VERSION 5.7 ;
  NOWIREEXTENSIONATPIN ON ;
  DIVIDERCHAR "/" ;
  BUSBITCHARS "[]" ;
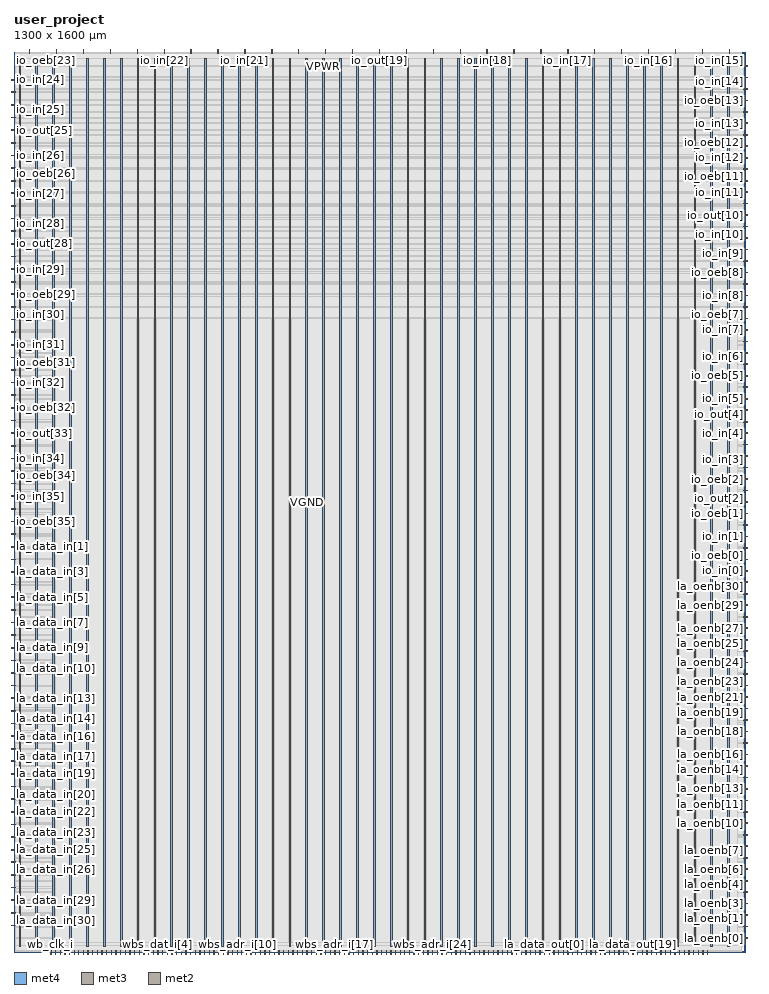
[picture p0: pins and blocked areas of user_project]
MACRO user_project
  CLASS BLOCK ;
  FOREIGN user_project ;
  ORIGIN 0.000 0.000 ;
  SIZE 1300.000 BY 1600.000 ;
  PIN VGND
    DIRECTION INOUT ;
    USE GROUND ;
    PORT
      LAYER met4 ;
        RECT 38.970 10.640 42.070 1588.720 ;
    END
    PORT
      LAYER met4 ;
        RECT 98.970 10.640 102.070 1588.720 ;
    END
    PORT
      LAYER met4 ;
        RECT 158.970 10.640 162.070 1588.720 ;
    END
    PORT
      LAYER met4 ;
        RECT 218.970 10.640 222.070 1588.720 ;
    END
    PORT
      LAYER met4 ;
        RECT 278.970 10.640 282.070 1588.720 ;
    END
    PORT
      LAYER met4 ;
        RECT 338.970 10.640 342.070 1588.720 ;
    END
    PORT
      LAYER met4 ;
        RECT 398.970 10.640 402.070 1588.720 ;
    END
    PORT
      LAYER met4 ;
        RECT 458.970 10.640 462.070 1588.720 ;
    END
    PORT
      LAYER met4 ;
        RECT 518.970 10.640 522.070 1588.720 ;
    END
    PORT
      LAYER met4 ;
        RECT 578.970 10.640 582.070 1588.720 ;
    END
    PORT
      LAYER met4 ;
        RECT 638.970 10.640 642.070 1588.720 ;
    END
    PORT
      LAYER met4 ;
        RECT 698.970 10.640 702.070 1588.720 ;
    END
    PORT
      LAYER met4 ;
        RECT 758.970 10.640 762.070 1588.720 ;
    END
    PORT
      LAYER met4 ;
        RECT 818.970 10.640 822.070 1588.720 ;
    END
    PORT
      LAYER met4 ;
        RECT 878.970 10.640 882.070 1588.720 ;
    END
    PORT
      LAYER met4 ;
        RECT 938.970 10.640 942.070 1588.720 ;
    END
    PORT
      LAYER met4 ;
        RECT 998.970 10.640 1002.070 1588.720 ;
    END
    PORT
      LAYER met4 ;
        RECT 1058.970 10.640 1062.070 1588.720 ;
    END
    PORT
      LAYER met4 ;
        RECT 1118.970 10.640 1122.070 1588.720 ;
    END
    PORT
      LAYER met4 ;
        RECT 1178.970 10.640 1182.070 1588.720 ;
    END
    PORT
      LAYER met4 ;
        RECT 1238.970 10.640 1242.070 1588.720 ;
    END
  END VGND
  PIN VPWR
    DIRECTION INOUT ;
    USE POWER ;
    PORT
      LAYER met4 ;
        RECT 8.970 10.640 12.070 1588.720 ;
    END
    PORT
      LAYER met4 ;
        RECT 68.970 10.640 72.070 1588.720 ;
    END
    PORT
      LAYER met4 ;
        RECT 128.970 10.640 132.070 1588.720 ;
    END
    PORT
      LAYER met4 ;
        RECT 188.970 10.640 192.070 1588.720 ;
    END
    PORT
      LAYER met4 ;
        RECT 248.970 10.640 252.070 1588.720 ;
    END
    PORT
      LAYER met4 ;
        RECT 308.970 10.640 312.070 1588.720 ;
    END
    PORT
      LAYER met4 ;
        RECT 368.970 10.640 372.070 1588.720 ;
    END
    PORT
      LAYER met4 ;
        RECT 428.970 10.640 432.070 1588.720 ;
    END
    PORT
      LAYER met4 ;
        RECT 488.970 10.640 492.070 1588.720 ;
    END
    PORT
      LAYER met4 ;
        RECT 548.970 10.640 552.070 1588.720 ;
    END
    PORT
      LAYER met4 ;
        RECT 608.970 10.640 612.070 1588.720 ;
    END
    PORT
      LAYER met4 ;
        RECT 668.970 10.640 672.070 1588.720 ;
    END
    PORT
      LAYER met4 ;
        RECT 728.970 10.640 732.070 1588.720 ;
    END
    PORT
      LAYER met4 ;
        RECT 788.970 10.640 792.070 1588.720 ;
    END
    PORT
      LAYER met4 ;
        RECT 848.970 10.640 852.070 1588.720 ;
    END
    PORT
      LAYER met4 ;
        RECT 908.970 10.640 912.070 1588.720 ;
    END
    PORT
      LAYER met4 ;
        RECT 968.970 10.640 972.070 1588.720 ;
    END
    PORT
      LAYER met4 ;
        RECT 1028.970 10.640 1032.070 1588.720 ;
    END
    PORT
      LAYER met4 ;
        RECT 1088.970 10.640 1092.070 1588.720 ;
    END
    PORT
      LAYER met4 ;
        RECT 1148.970 10.640 1152.070 1588.720 ;
    END
    PORT
      LAYER met4 ;
        RECT 1208.970 10.640 1212.070 1588.720 ;
    END
    PORT
      LAYER met4 ;
        RECT 1268.970 10.640 1272.070 1588.720 ;
    END
  END VPWR
  PIN io_in[0]
    DIRECTION INPUT ;
    USE SIGNAL ;
    PORT
      LAYER met3 ;
        RECT 1297.600 677.020 1304.800 678.220 ;
    END
  END io_in[0]
  PIN io_in[10]
    DIRECTION INPUT ;
    USE SIGNAL ;
    PORT
      LAYER met3 ;
        RECT 1297.600 1289.020 1304.800 1290.220 ;
    END
  END io_in[10]
  PIN io_in[11]
    DIRECTION INPUT ;
    USE SIGNAL ;
    PORT
      LAYER met3 ;
        RECT 1297.600 1350.220 1304.800 1351.420 ;
    END
  END io_in[11]
  PIN io_in[12]
    DIRECTION INPUT ;
    USE SIGNAL ;
    PORT
      LAYER met3 ;
        RECT 1297.600 1411.420 1304.800 1412.620 ;
    END
  END io_in[12]
  PIN io_in[13]
    DIRECTION INPUT ;
    USE SIGNAL ;
    PORT
      LAYER met3 ;
        RECT 1297.600 1472.620 1304.800 1473.820 ;
    END
  END io_in[13]
  PIN io_in[14]
    DIRECTION INPUT ;
    USE SIGNAL ;
    PORT
      LAYER met3 ;
        RECT 1297.600 1533.820 1304.800 1535.020 ;
    END
  END io_in[14]
  PIN io_in[15]
    DIRECTION INPUT ;
    USE SIGNAL ;
    PORT
      LAYER met2 ;
        RECT 1271.390 1597.600 1271.950 1604.800 ;
    END
  END io_in[15]
  PIN io_in[16]
    DIRECTION INPUT ;
    USE SIGNAL ;
    PORT
      LAYER met2 ;
        RECT 1127.870 1597.600 1128.430 1604.800 ;
    END
  END io_in[16]
  PIN io_in[17]
    DIRECTION INPUT ;
    USE SIGNAL ;
    PORT
      LAYER met2 ;
        RECT 984.350 1597.600 984.910 1604.800 ;
    END
  END io_in[17]
  PIN io_in[18]
    DIRECTION INPUT ;
    USE SIGNAL ;
    PORT
      LAYER met2 ;
        RECT 840.830 1597.600 841.390 1604.800 ;
    END
  END io_in[18]
  PIN io_in[19]
    DIRECTION INPUT ;
    USE SIGNAL ;
    PORT
      LAYER met2 ;
        RECT 697.310 1597.600 697.870 1604.800 ;
    END
  END io_in[19]
  PIN io_in[1]
    DIRECTION INPUT ;
    USE SIGNAL ;
    PORT
      LAYER met3 ;
        RECT 1297.600 738.220 1304.800 739.420 ;
    END
  END io_in[1]
  PIN io_in[20]
    DIRECTION INPUT ;
    USE SIGNAL ;
    PORT
      LAYER met2 ;
        RECT 553.790 1597.600 554.350 1604.800 ;
    END
  END io_in[20]
  PIN io_in[21]
    DIRECTION INPUT ;
    USE SIGNAL ;
    PORT
      LAYER met2 ;
        RECT 410.270 1597.600 410.830 1604.800 ;
    END
  END io_in[21]
  PIN io_in[22]
    DIRECTION INPUT ;
    USE SIGNAL ;
    PORT
      LAYER met2 ;
        RECT 266.750 1597.600 267.310 1604.800 ;
    END
  END io_in[22]
  PIN io_in[23]
    DIRECTION INPUT ;
    USE SIGNAL ;
    PORT
      LAYER met2 ;
        RECT 123.230 1597.600 123.790 1604.800 ;
    END
  END io_in[23]
  PIN io_in[24]
    DIRECTION INPUT ;
    USE SIGNAL ;
    PORT
      LAYER met3 ;
        RECT -4.800 1550.140 2.400 1551.340 ;
    END
  END io_in[24]
  PIN io_in[25]
    DIRECTION INPUT ;
    USE SIGNAL ;
    PORT
      LAYER met3 ;
        RECT -4.800 1482.820 2.400 1484.020 ;
    END
  END io_in[25]
  PIN io_in[26]
    DIRECTION INPUT ;
    USE SIGNAL ;
    PORT
      LAYER met3 ;
        RECT -4.800 1415.500 2.400 1416.700 ;
    END
  END io_in[26]
  PIN io_in[27]
    DIRECTION INPUT ;
    USE SIGNAL ;
    PORT
      LAYER met3 ;
        RECT -4.800 1348.180 2.400 1349.380 ;
    END
  END io_in[27]
  PIN io_in[28]
    DIRECTION INPUT ;
    USE SIGNAL ;
    PORT
      LAYER met3 ;
        RECT -4.800 1280.860 2.400 1282.060 ;
    END
  END io_in[28]
  PIN io_in[29]
    DIRECTION INPUT ;
    USE SIGNAL ;
    PORT
      LAYER met3 ;
        RECT -4.800 1213.540 2.400 1214.740 ;
    END
  END io_in[29]
  PIN io_in[2]
    DIRECTION INPUT ;
    USE SIGNAL ;
    PORT
      LAYER met3 ;
        RECT 1297.600 799.420 1304.800 800.620 ;
    END
  END io_in[2]
  PIN io_in[30]
    DIRECTION INPUT ;
    USE SIGNAL ;
    PORT
      LAYER met3 ;
        RECT -4.800 1146.220 2.400 1147.420 ;
    END
  END io_in[30]
  PIN io_in[31]
    DIRECTION INPUT ;
    USE SIGNAL ;
    PORT
      LAYER met3 ;
        RECT -4.800 1078.900 2.400 1080.100 ;
    END
  END io_in[31]
  PIN io_in[32]
    DIRECTION INPUT ;
    USE SIGNAL ;
    PORT
      LAYER met3 ;
        RECT -4.800 1011.580 2.400 1012.780 ;
    END
  END io_in[32]
  PIN io_in[33]
    DIRECTION INPUT ;
    USE SIGNAL ;
    PORT
      LAYER met3 ;
        RECT -4.800 944.260 2.400 945.460 ;
    END
  END io_in[33]
  PIN io_in[34]
    DIRECTION INPUT ;
    USE SIGNAL ;
    PORT
      LAYER met3 ;
        RECT -4.800 876.940 2.400 878.140 ;
    END
  END io_in[34]
  PIN io_in[35]
    DIRECTION INPUT ;
    USE SIGNAL ;
    PORT
      LAYER met3 ;
        RECT -4.800 809.620 2.400 810.820 ;
    END
  END io_in[35]
  PIN io_in[3]
    DIRECTION INPUT ;
    USE SIGNAL ;
    PORT
      LAYER met3 ;
        RECT 1297.600 860.620 1304.800 861.820 ;
    END
  END io_in[3]
  PIN io_in[4]
    DIRECTION INPUT ;
    USE SIGNAL ;
    PORT
      LAYER met3 ;
        RECT 1297.600 921.820 1304.800 923.020 ;
    END
  END io_in[4]
  PIN io_in[5]
    DIRECTION INPUT ;
    USE SIGNAL ;
    PORT
      LAYER met3 ;
        RECT 1297.600 983.020 1304.800 984.220 ;
    END
  END io_in[5]
  PIN io_in[6]
    DIRECTION INPUT ;
    USE SIGNAL ;
    PORT
      LAYER met3 ;
        RECT 1297.600 1044.220 1304.800 1045.420 ;
    END
  END io_in[6]
  PIN io_in[7]
    DIRECTION INPUT ;
    USE SIGNAL ;
    PORT
      LAYER met3 ;
        RECT 1297.600 1105.420 1304.800 1106.620 ;
    END
  END io_in[7]
  PIN io_in[8]
    DIRECTION INPUT ;
    USE SIGNAL ;
    PORT
      LAYER met3 ;
        RECT 1297.600 1166.620 1304.800 1167.820 ;
    END
  END io_in[8]
  PIN io_in[9]
    DIRECTION INPUT ;
    USE SIGNAL ;
    PORT
      LAYER met3 ;
        RECT 1297.600 1227.820 1304.800 1229.020 ;
    END
  END io_in[9]
  PIN io_oeb[0]
    DIRECTION OUTPUT ;
    USE SIGNAL ;
    ANTENNADIFFAREA 2.673000 ;
    PORT
      LAYER met3 ;
        RECT 1297.600 717.820 1304.800 719.020 ;
    END
  END io_oeb[0]
  PIN io_oeb[10]
    DIRECTION OUTPUT ;
    USE SIGNAL ;
    ANTENNADIFFAREA 2.673000 ;
    PORT
      LAYER met3 ;
        RECT 1297.600 1329.820 1304.800 1331.020 ;
    END
  END io_oeb[10]
  PIN io_oeb[11]
    DIRECTION OUTPUT ;
    USE SIGNAL ;
    ANTENNADIFFAREA 2.673000 ;
    PORT
      LAYER met3 ;
        RECT 1297.600 1391.020 1304.800 1392.220 ;
    END
  END io_oeb[11]
  PIN io_oeb[12]
    DIRECTION OUTPUT ;
    USE SIGNAL ;
    ANTENNADIFFAREA 2.673000 ;
    PORT
      LAYER met3 ;
        RECT 1297.600 1452.220 1304.800 1453.420 ;
    END
  END io_oeb[12]
  PIN io_oeb[13]
    DIRECTION OUTPUT ;
    USE SIGNAL ;
    ANTENNADIFFAREA 2.673000 ;
    PORT
      LAYER met3 ;
        RECT 1297.600 1513.420 1304.800 1514.620 ;
    END
  END io_oeb[13]
  PIN io_oeb[14]
    DIRECTION OUTPUT ;
    USE SIGNAL ;
    ANTENNADIFFAREA 2.673000 ;
    PORT
      LAYER met3 ;
        RECT 1297.600 1574.620 1304.800 1575.820 ;
    END
  END io_oeb[14]
  PIN io_oeb[15]
    DIRECTION OUTPUT ;
    USE SIGNAL ;
    ANTENNADIFFAREA 2.673000 ;
    PORT
      LAYER met2 ;
        RECT 1175.710 1597.600 1176.270 1604.800 ;
    END
  END io_oeb[15]
  PIN io_oeb[16]
    DIRECTION OUTPUT ;
    USE SIGNAL ;
    ANTENNADIFFAREA 2.673000 ;
    PORT
      LAYER met2 ;
        RECT 1032.190 1597.600 1032.750 1604.800 ;
    END
  END io_oeb[16]
  PIN io_oeb[17]
    DIRECTION OUTPUT ;
    USE SIGNAL ;
    ANTENNADIFFAREA 2.673000 ;
    PORT
      LAYER met2 ;
        RECT 888.670 1597.600 889.230 1604.800 ;
    END
  END io_oeb[17]
  PIN io_oeb[18]
    DIRECTION OUTPUT ;
    USE SIGNAL ;
    ANTENNADIFFAREA 2.673000 ;
    PORT
      LAYER met2 ;
        RECT 745.150 1597.600 745.710 1604.800 ;
    END
  END io_oeb[18]
  PIN io_oeb[19]
    DIRECTION OUTPUT ;
    USE SIGNAL ;
    ANTENNADIFFAREA 2.673000 ;
    PORT
      LAYER met2 ;
        RECT 601.630 1597.600 602.190 1604.800 ;
    END
  END io_oeb[19]
  PIN io_oeb[1]
    DIRECTION OUTPUT ;
    USE SIGNAL ;
    ANTENNADIFFAREA 2.673000 ;
    PORT
      LAYER met3 ;
        RECT 1297.600 779.020 1304.800 780.220 ;
    END
  END io_oeb[1]
  PIN io_oeb[20]
    DIRECTION OUTPUT ;
    USE SIGNAL ;
    ANTENNADIFFAREA 2.673000 ;
    PORT
      LAYER met2 ;
        RECT 458.110 1597.600 458.670 1604.800 ;
    END
  END io_oeb[20]
  PIN io_oeb[21]
    DIRECTION OUTPUT ;
    USE SIGNAL ;
    ANTENNADIFFAREA 2.673000 ;
    PORT
      LAYER met2 ;
        RECT 314.590 1597.600 315.150 1604.800 ;
    END
  END io_oeb[21]
  PIN io_oeb[22]
    DIRECTION OUTPUT ;
    USE SIGNAL ;
    ANTENNADIFFAREA 2.673000 ;
    PORT
      LAYER met2 ;
        RECT 171.070 1597.600 171.630 1604.800 ;
    END
  END io_oeb[22]
  PIN io_oeb[23]
    DIRECTION OUTPUT ;
    USE SIGNAL ;
    ANTENNADIFFAREA 2.673000 ;
    PORT
      LAYER met2 ;
        RECT 27.550 1597.600 28.110 1604.800 ;
    END
  END io_oeb[23]
  PIN io_oeb[24]
    DIRECTION OUTPUT ;
    USE SIGNAL ;
    ANTENNADIFFAREA 2.673000 ;
    PORT
      LAYER met3 ;
        RECT -4.800 1505.260 2.400 1506.460 ;
    END
  END io_oeb[24]
  PIN io_oeb[25]
    DIRECTION OUTPUT ;
    USE SIGNAL ;
    ANTENNADIFFAREA 2.673000 ;
    PORT
      LAYER met3 ;
        RECT -4.800 1437.940 2.400 1439.140 ;
    END
  END io_oeb[25]
  PIN io_oeb[26]
    DIRECTION OUTPUT ;
    USE SIGNAL ;
    ANTENNADIFFAREA 2.673000 ;
    PORT
      LAYER met3 ;
        RECT -4.800 1370.620 2.400 1371.820 ;
    END
  END io_oeb[26]
  PIN io_oeb[27]
    DIRECTION OUTPUT ;
    USE SIGNAL ;
    ANTENNADIFFAREA 2.673000 ;
    PORT
      LAYER met3 ;
        RECT -4.800 1303.300 2.400 1304.500 ;
    END
  END io_oeb[27]
  PIN io_oeb[28]
    DIRECTION OUTPUT ;
    USE SIGNAL ;
    ANTENNADIFFAREA 2.673000 ;
    PORT
      LAYER met3 ;
        RECT -4.800 1235.980 2.400 1237.180 ;
    END
  END io_oeb[28]
  PIN io_oeb[29]
    DIRECTION OUTPUT ;
    USE SIGNAL ;
    ANTENNADIFFAREA 2.673000 ;
    PORT
      LAYER met3 ;
        RECT -4.800 1168.660 2.400 1169.860 ;
    END
  END io_oeb[29]
  PIN io_oeb[2]
    DIRECTION OUTPUT ;
    USE SIGNAL ;
    ANTENNADIFFAREA 2.673000 ;
    PORT
      LAYER met3 ;
        RECT 1297.600 840.220 1304.800 841.420 ;
    END
  END io_oeb[2]
  PIN io_oeb[30]
    DIRECTION OUTPUT ;
    USE SIGNAL ;
    PORT
      LAYER met3 ;
        RECT -4.800 1101.340 2.400 1102.540 ;
    END
  END io_oeb[30]
  PIN io_oeb[31]
    DIRECTION OUTPUT ;
    USE SIGNAL ;
    PORT
      LAYER met3 ;
        RECT -4.800 1034.020 2.400 1035.220 ;
    END
  END io_oeb[31]
  PIN io_oeb[32]
    DIRECTION OUTPUT ;
    USE SIGNAL ;
    PORT
      LAYER met3 ;
        RECT -4.800 966.700 2.400 967.900 ;
    END
  END io_oeb[32]
  PIN io_oeb[33]
    DIRECTION OUTPUT ;
    USE SIGNAL ;
    PORT
      LAYER met3 ;
        RECT -4.800 899.380 2.400 900.580 ;
    END
  END io_oeb[33]
  PIN io_oeb[34]
    DIRECTION OUTPUT ;
    USE SIGNAL ;
    PORT
      LAYER met3 ;
        RECT -4.800 832.060 2.400 833.260 ;
    END
  END io_oeb[34]
  PIN io_oeb[35]
    DIRECTION OUTPUT ;
    USE SIGNAL ;
    PORT
      LAYER met3 ;
        RECT -4.800 764.740 2.400 765.940 ;
    END
  END io_oeb[35]
  PIN io_oeb[3]
    DIRECTION OUTPUT ;
    USE SIGNAL ;
    ANTENNADIFFAREA 2.673000 ;
    PORT
      LAYER met3 ;
        RECT 1297.600 901.420 1304.800 902.620 ;
    END
  END io_oeb[3]
  PIN io_oeb[4]
    DIRECTION OUTPUT ;
    USE SIGNAL ;
    ANTENNADIFFAREA 2.673000 ;
    PORT
      LAYER met3 ;
        RECT 1297.600 962.620 1304.800 963.820 ;
    END
  END io_oeb[4]
  PIN io_oeb[5]
    DIRECTION OUTPUT ;
    USE SIGNAL ;
    ANTENNADIFFAREA 2.673000 ;
    PORT
      LAYER met3 ;
        RECT 1297.600 1023.820 1304.800 1025.020 ;
    END
  END io_oeb[5]
  PIN io_oeb[6]
    DIRECTION OUTPUT ;
    USE SIGNAL ;
    ANTENNADIFFAREA 2.673000 ;
    PORT
      LAYER met3 ;
        RECT 1297.600 1085.020 1304.800 1086.220 ;
    END
  END io_oeb[6]
  PIN io_oeb[7]
    DIRECTION OUTPUT ;
    USE SIGNAL ;
    ANTENNADIFFAREA 2.673000 ;
    PORT
      LAYER met3 ;
        RECT 1297.600 1146.220 1304.800 1147.420 ;
    END
  END io_oeb[7]
  PIN io_oeb[8]
    DIRECTION OUTPUT ;
    USE SIGNAL ;
    ANTENNADIFFAREA 2.673000 ;
    PORT
      LAYER met3 ;
        RECT 1297.600 1207.420 1304.800 1208.620 ;
    END
  END io_oeb[8]
  PIN io_oeb[9]
    DIRECTION OUTPUT ;
    USE SIGNAL ;
    ANTENNADIFFAREA 2.673000 ;
    PORT
      LAYER met3 ;
        RECT 1297.600 1268.620 1304.800 1269.820 ;
    END
  END io_oeb[9]
  PIN io_out[0]
    DIRECTION OUTPUT ;
    USE SIGNAL ;
    ANTENNADIFFAREA 2.673000 ;
    PORT
      LAYER met3 ;
        RECT 1297.600 697.420 1304.800 698.620 ;
    END
  END io_out[0]
  PIN io_out[10]
    DIRECTION OUTPUT ;
    USE SIGNAL ;
    ANTENNADIFFAREA 2.673000 ;
    PORT
      LAYER met3 ;
        RECT 1297.600 1309.420 1304.800 1310.620 ;
    END
  END io_out[10]
  PIN io_out[11]
    DIRECTION OUTPUT ;
    USE SIGNAL ;
    ANTENNADIFFAREA 2.673000 ;
    PORT
      LAYER met3 ;
        RECT 1297.600 1370.620 1304.800 1371.820 ;
    END
  END io_out[11]
  PIN io_out[12]
    DIRECTION OUTPUT ;
    USE SIGNAL ;
    ANTENNADIFFAREA 2.673000 ;
    PORT
      LAYER met3 ;
        RECT 1297.600 1431.820 1304.800 1433.020 ;
    END
  END io_out[12]
  PIN io_out[13]
    DIRECTION OUTPUT ;
    USE SIGNAL ;
    ANTENNADIFFAREA 2.673000 ;
    PORT
      LAYER met3 ;
        RECT 1297.600 1493.020 1304.800 1494.220 ;
    END
  END io_out[13]
  PIN io_out[14]
    DIRECTION OUTPUT ;
    USE SIGNAL ;
    ANTENNADIFFAREA 2.673000 ;
    PORT
      LAYER met3 ;
        RECT 1297.600 1554.220 1304.800 1555.420 ;
    END
  END io_out[14]
  PIN io_out[15]
    DIRECTION OUTPUT ;
    USE SIGNAL ;
    ANTENNADIFFAREA 2.673000 ;
    PORT
      LAYER met2 ;
        RECT 1223.550 1597.600 1224.110 1604.800 ;
    END
  END io_out[15]
  PIN io_out[16]
    DIRECTION OUTPUT ;
    USE SIGNAL ;
    ANTENNADIFFAREA 2.673000 ;
    PORT
      LAYER met2 ;
        RECT 1080.030 1597.600 1080.590 1604.800 ;
    END
  END io_out[16]
  PIN io_out[17]
    DIRECTION OUTPUT ;
    USE SIGNAL ;
    ANTENNADIFFAREA 2.673000 ;
    PORT
      LAYER met2 ;
        RECT 936.510 1597.600 937.070 1604.800 ;
    END
  END io_out[17]
  PIN io_out[18]
    DIRECTION OUTPUT ;
    USE SIGNAL ;
    ANTENNADIFFAREA 2.673000 ;
    PORT
      LAYER met2 ;
        RECT 792.990 1597.600 793.550 1604.800 ;
    END
  END io_out[18]
  PIN io_out[19]
    DIRECTION OUTPUT ;
    USE SIGNAL ;
    ANTENNADIFFAREA 2.673000 ;
    PORT
      LAYER met2 ;
        RECT 649.470 1597.600 650.030 1604.800 ;
    END
  END io_out[19]
  PIN io_out[1]
    DIRECTION OUTPUT ;
    USE SIGNAL ;
    ANTENNADIFFAREA 2.673000 ;
    PORT
      LAYER met3 ;
        RECT 1297.600 758.620 1304.800 759.820 ;
    END
  END io_out[1]
  PIN io_out[20]
    DIRECTION OUTPUT ;
    USE SIGNAL ;
    ANTENNADIFFAREA 2.673000 ;
    PORT
      LAYER met2 ;
        RECT 505.950 1597.600 506.510 1604.800 ;
    END
  END io_out[20]
  PIN io_out[21]
    DIRECTION OUTPUT ;
    USE SIGNAL ;
    ANTENNADIFFAREA 2.673000 ;
    PORT
      LAYER met2 ;
        RECT 362.430 1597.600 362.990 1604.800 ;
    END
  END io_out[21]
  PIN io_out[22]
    DIRECTION OUTPUT ;
    USE SIGNAL ;
    ANTENNADIFFAREA 2.673000 ;
    PORT
      LAYER met2 ;
        RECT 218.910 1597.600 219.470 1604.800 ;
    END
  END io_out[22]
  PIN io_out[23]
    DIRECTION OUTPUT ;
    USE SIGNAL ;
    ANTENNADIFFAREA 2.673000 ;
    PORT
      LAYER met2 ;
        RECT 75.390 1597.600 75.950 1604.800 ;
    END
  END io_out[23]
  PIN io_out[24]
    DIRECTION OUTPUT ;
    USE SIGNAL ;
    ANTENNADIFFAREA 2.673000 ;
    PORT
      LAYER met3 ;
        RECT -4.800 1527.700 2.400 1528.900 ;
    END
  END io_out[24]
  PIN io_out[25]
    DIRECTION OUTPUT ;
    USE SIGNAL ;
    ANTENNADIFFAREA 2.673000 ;
    PORT
      LAYER met3 ;
        RECT -4.800 1460.380 2.400 1461.580 ;
    END
  END io_out[25]
  PIN io_out[26]
    DIRECTION OUTPUT ;
    USE SIGNAL ;
    ANTENNADIFFAREA 2.673000 ;
    PORT
      LAYER met3 ;
        RECT -4.800 1393.060 2.400 1394.260 ;
    END
  END io_out[26]
  PIN io_out[27]
    DIRECTION OUTPUT ;
    USE SIGNAL ;
    ANTENNADIFFAREA 2.673000 ;
    PORT
      LAYER met3 ;
        RECT -4.800 1325.740 2.400 1326.940 ;
    END
  END io_out[27]
  PIN io_out[28]
    DIRECTION OUTPUT ;
    USE SIGNAL ;
    ANTENNADIFFAREA 2.673000 ;
    PORT
      LAYER met3 ;
        RECT -4.800 1258.420 2.400 1259.620 ;
    END
  END io_out[28]
  PIN io_out[29]
    DIRECTION OUTPUT ;
    USE SIGNAL ;
    ANTENNADIFFAREA 2.673000 ;
    PORT
      LAYER met3 ;
        RECT -4.800 1191.100 2.400 1192.300 ;
    END
  END io_out[29]
  PIN io_out[2]
    DIRECTION OUTPUT ;
    USE SIGNAL ;
    ANTENNADIFFAREA 2.673000 ;
    PORT
      LAYER met3 ;
        RECT 1297.600 819.820 1304.800 821.020 ;
    END
  END io_out[2]
  PIN io_out[30]
    DIRECTION OUTPUT ;
    USE SIGNAL ;
    PORT
      LAYER met3 ;
        RECT -4.800 1123.780 2.400 1124.980 ;
    END
  END io_out[30]
  PIN io_out[31]
    DIRECTION OUTPUT ;
    USE SIGNAL ;
    PORT
      LAYER met3 ;
        RECT -4.800 1056.460 2.400 1057.660 ;
    END
  END io_out[31]
  PIN io_out[32]
    DIRECTION OUTPUT ;
    USE SIGNAL ;
    PORT
      LAYER met3 ;
        RECT -4.800 989.140 2.400 990.340 ;
    END
  END io_out[32]
  PIN io_out[33]
    DIRECTION OUTPUT ;
    USE SIGNAL ;
    PORT
      LAYER met3 ;
        RECT -4.800 921.820 2.400 923.020 ;
    END
  END io_out[33]
  PIN io_out[34]
    DIRECTION OUTPUT ;
    USE SIGNAL ;
    PORT
      LAYER met3 ;
        RECT -4.800 854.500 2.400 855.700 ;
    END
  END io_out[34]
  PIN io_out[35]
    DIRECTION OUTPUT ;
    USE SIGNAL ;
    PORT
      LAYER met3 ;
        RECT -4.800 787.180 2.400 788.380 ;
    END
  END io_out[35]
  PIN io_out[3]
    DIRECTION OUTPUT ;
    USE SIGNAL ;
    ANTENNADIFFAREA 2.673000 ;
    PORT
      LAYER met3 ;
        RECT 1297.600 881.020 1304.800 882.220 ;
    END
  END io_out[3]
  PIN io_out[4]
    DIRECTION OUTPUT ;
    USE SIGNAL ;
    ANTENNADIFFAREA 2.673000 ;
    PORT
      LAYER met3 ;
        RECT 1297.600 942.220 1304.800 943.420 ;
    END
  END io_out[4]
  PIN io_out[5]
    DIRECTION OUTPUT ;
    USE SIGNAL ;
    ANTENNADIFFAREA 2.673000 ;
    PORT
      LAYER met3 ;
        RECT 1297.600 1003.420 1304.800 1004.620 ;
    END
  END io_out[5]
  PIN io_out[6]
    DIRECTION OUTPUT ;
    USE SIGNAL ;
    ANTENNADIFFAREA 2.673000 ;
    PORT
      LAYER met3 ;
        RECT 1297.600 1064.620 1304.800 1065.820 ;
    END
  END io_out[6]
  PIN io_out[7]
    DIRECTION OUTPUT ;
    USE SIGNAL ;
    ANTENNADIFFAREA 2.673000 ;
    PORT
      LAYER met3 ;
        RECT 1297.600 1125.820 1304.800 1127.020 ;
    END
  END io_out[7]
  PIN io_out[8]
    DIRECTION OUTPUT ;
    USE SIGNAL ;
    ANTENNADIFFAREA 2.673000 ;
    PORT
      LAYER met3 ;
        RECT 1297.600 1187.020 1304.800 1188.220 ;
    END
  END io_out[8]
  PIN io_out[9]
    DIRECTION OUTPUT ;
    USE SIGNAL ;
    ANTENNADIFFAREA 2.673000 ;
    PORT
      LAYER met3 ;
        RECT 1297.600 1248.220 1304.800 1249.420 ;
    END
  END io_out[9]
  PIN la_data_in[0]
    DIRECTION INPUT ;
    USE SIGNAL ;
    ANTENNAGATEAREA 0.126000 ;
    PORT
      LAYER met3 ;
        RECT -4.800 742.300 2.400 743.500 ;
    END
  END la_data_in[0]
  PIN la_data_in[10]
    DIRECTION INPUT ;
    USE SIGNAL ;
    ANTENNAGATEAREA 0.126000 ;
    PORT
      LAYER met3 ;
        RECT -4.800 517.900 2.400 519.100 ;
    END
  END la_data_in[10]
  PIN la_data_in[11]
    DIRECTION INPUT ;
    USE SIGNAL ;
    ANTENNAGATEAREA 0.126000 ;
    PORT
      LAYER met3 ;
        RECT -4.800 495.460 2.400 496.660 ;
    END
  END la_data_in[11]
  PIN la_data_in[12]
    DIRECTION INPUT ;
    USE SIGNAL ;
    ANTENNAGATEAREA 0.126000 ;
    PORT
      LAYER met3 ;
        RECT -4.800 473.020 2.400 474.220 ;
    END
  END la_data_in[12]
  PIN la_data_in[13]
    DIRECTION INPUT ;
    USE SIGNAL ;
    ANTENNAGATEAREA 0.126000 ;
    PORT
      LAYER met3 ;
        RECT -4.800 450.580 2.400 451.780 ;
    END
  END la_data_in[13]
  PIN la_data_in[14]
    DIRECTION INPUT ;
    USE SIGNAL ;
    ANTENNAGATEAREA 0.126000 ;
    PORT
      LAYER met3 ;
        RECT -4.800 428.140 2.400 429.340 ;
    END
  END la_data_in[14]
  PIN la_data_in[15]
    DIRECTION INPUT ;
    USE SIGNAL ;
    ANTENNAGATEAREA 0.126000 ;
    PORT
      LAYER met3 ;
        RECT -4.800 405.700 2.400 406.900 ;
    END
  END la_data_in[15]
  PIN la_data_in[16]
    DIRECTION INPUT ;
    USE SIGNAL ;
    ANTENNAGATEAREA 0.126000 ;
    PORT
      LAYER met3 ;
        RECT -4.800 383.260 2.400 384.460 ;
    END
  END la_data_in[16]
  PIN la_data_in[17]
    DIRECTION INPUT ;
    USE SIGNAL ;
    ANTENNAGATEAREA 0.126000 ;
    PORT
      LAYER met3 ;
        RECT -4.800 360.820 2.400 362.020 ;
    END
  END la_data_in[17]
  PIN la_data_in[18]
    DIRECTION INPUT ;
    USE SIGNAL ;
    ANTENNAGATEAREA 0.126000 ;
    PORT
      LAYER met3 ;
        RECT -4.800 338.380 2.400 339.580 ;
    END
  END la_data_in[18]
  PIN la_data_in[19]
    DIRECTION INPUT ;
    USE SIGNAL ;
    ANTENNAGATEAREA 0.126000 ;
    PORT
      LAYER met3 ;
        RECT -4.800 315.940 2.400 317.140 ;
    END
  END la_data_in[19]
  PIN la_data_in[1]
    DIRECTION INPUT ;
    USE SIGNAL ;
    ANTENNAGATEAREA 0.126000 ;
    PORT
      LAYER met3 ;
        RECT -4.800 719.860 2.400 721.060 ;
    END
  END la_data_in[1]
  PIN la_data_in[20]
    DIRECTION INPUT ;
    USE SIGNAL ;
    ANTENNAGATEAREA 0.126000 ;
    PORT
      LAYER met3 ;
        RECT -4.800 293.500 2.400 294.700 ;
    END
  END la_data_in[20]
  PIN la_data_in[21]
    DIRECTION INPUT ;
    USE SIGNAL ;
    ANTENNAGATEAREA 0.126000 ;
    PORT
      LAYER met3 ;
        RECT -4.800 271.060 2.400 272.260 ;
    END
  END la_data_in[21]
  PIN la_data_in[22]
    DIRECTION INPUT ;
    USE SIGNAL ;
    ANTENNAGATEAREA 0.126000 ;
    PORT
      LAYER met3 ;
        RECT -4.800 248.620 2.400 249.820 ;
    END
  END la_data_in[22]
  PIN la_data_in[23]
    DIRECTION INPUT ;
    USE SIGNAL ;
    ANTENNAGATEAREA 0.126000 ;
    PORT
      LAYER met3 ;
        RECT -4.800 226.180 2.400 227.380 ;
    END
  END la_data_in[23]
  PIN la_data_in[24]
    DIRECTION INPUT ;
    USE SIGNAL ;
    ANTENNAGATEAREA 0.126000 ;
    PORT
      LAYER met3 ;
        RECT -4.800 203.740 2.400 204.940 ;
    END
  END la_data_in[24]
  PIN la_data_in[25]
    DIRECTION INPUT ;
    USE SIGNAL ;
    ANTENNAGATEAREA 0.126000 ;
    PORT
      LAYER met3 ;
        RECT -4.800 181.300 2.400 182.500 ;
    END
  END la_data_in[25]
  PIN la_data_in[26]
    DIRECTION INPUT ;
    USE SIGNAL ;
    ANTENNAGATEAREA 0.126000 ;
    PORT
      LAYER met3 ;
        RECT -4.800 158.860 2.400 160.060 ;
    END
  END la_data_in[26]
  PIN la_data_in[27]
    DIRECTION INPUT ;
    USE SIGNAL ;
    ANTENNAGATEAREA 0.126000 ;
    PORT
      LAYER met3 ;
        RECT -4.800 136.420 2.400 137.620 ;
    END
  END la_data_in[27]
  PIN la_data_in[28]
    DIRECTION INPUT ;
    USE SIGNAL ;
    ANTENNAGATEAREA 0.126000 ;
    PORT
      LAYER met3 ;
        RECT -4.800 113.980 2.400 115.180 ;
    END
  END la_data_in[28]
  PIN la_data_in[29]
    DIRECTION INPUT ;
    USE SIGNAL ;
    ANTENNAGATEAREA 0.126000 ;
    PORT
      LAYER met3 ;
        RECT -4.800 91.540 2.400 92.740 ;
    END
  END la_data_in[29]
  PIN la_data_in[2]
    DIRECTION INPUT ;
    USE SIGNAL ;
    ANTENNAGATEAREA 0.126000 ;
    PORT
      LAYER met3 ;
        RECT -4.800 697.420 2.400 698.620 ;
    END
  END la_data_in[2]
  PIN la_data_in[30]
    DIRECTION INPUT ;
    USE SIGNAL ;
    ANTENNAGATEAREA 0.196500 ;
    PORT
      LAYER met3 ;
        RECT -4.800 69.100 2.400 70.300 ;
    END
  END la_data_in[30]
  PIN la_data_in[31]
    DIRECTION INPUT ;
    USE SIGNAL ;
    ANTENNAGATEAREA 0.126000 ;
    PORT
      LAYER met3 ;
        RECT -4.800 46.660 2.400 47.860 ;
    END
  END la_data_in[31]
  PIN la_data_in[3]
    DIRECTION INPUT ;
    USE SIGNAL ;
    ANTENNAGATEAREA 0.126000 ;
    PORT
      LAYER met3 ;
        RECT -4.800 674.980 2.400 676.180 ;
    END
  END la_data_in[3]
  PIN la_data_in[4]
    DIRECTION INPUT ;
    USE SIGNAL ;
    ANTENNAGATEAREA 0.126000 ;
    PORT
      LAYER met3 ;
        RECT -4.800 652.540 2.400 653.740 ;
    END
  END la_data_in[4]
  PIN la_data_in[5]
    DIRECTION INPUT ;
    USE SIGNAL ;
    ANTENNAGATEAREA 0.126000 ;
    PORT
      LAYER met3 ;
        RECT -4.800 630.100 2.400 631.300 ;
    END
  END la_data_in[5]
  PIN la_data_in[6]
    DIRECTION INPUT ;
    USE SIGNAL ;
    ANTENNAGATEAREA 0.126000 ;
    PORT
      LAYER met3 ;
        RECT -4.800 607.660 2.400 608.860 ;
    END
  END la_data_in[6]
  PIN la_data_in[7]
    DIRECTION INPUT ;
    USE SIGNAL ;
    ANTENNAGATEAREA 0.126000 ;
    PORT
      LAYER met3 ;
        RECT -4.800 585.220 2.400 586.420 ;
    END
  END la_data_in[7]
  PIN la_data_in[8]
    DIRECTION INPUT ;
    USE SIGNAL ;
    ANTENNAGATEAREA 0.126000 ;
    PORT
      LAYER met3 ;
        RECT -4.800 562.780 2.400 563.980 ;
    END
  END la_data_in[8]
  PIN la_data_in[9]
    DIRECTION INPUT ;
    USE SIGNAL ;
    ANTENNAGATEAREA 0.126000 ;
    PORT
      LAYER met3 ;
        RECT -4.800 540.340 2.400 541.540 ;
    END
  END la_data_in[9]
  PIN la_data_out[0]
    DIRECTION OUTPUT ;
    USE SIGNAL ;
    PORT
      LAYER met2 ;
        RECT 942.950 -4.800 943.510 2.400 ;
    END
  END la_data_out[0]
  PIN la_data_out[10]
    DIRECTION OUTPUT ;
    USE SIGNAL ;
    PORT
      LAYER met2 ;
        RECT 1025.750 -4.800 1026.310 2.400 ;
    END
  END la_data_out[10]
  PIN la_data_out[11]
    DIRECTION OUTPUT ;
    USE SIGNAL ;
    PORT
      LAYER met2 ;
        RECT 1034.030 -4.800 1034.590 2.400 ;
    END
  END la_data_out[11]
  PIN la_data_out[12]
    DIRECTION OUTPUT ;
    USE SIGNAL ;
    PORT
      LAYER met2 ;
        RECT 1042.310 -4.800 1042.870 2.400 ;
    END
  END la_data_out[12]
  PIN la_data_out[13]
    DIRECTION OUTPUT ;
    USE SIGNAL ;
    PORT
      LAYER met2 ;
        RECT 1050.590 -4.800 1051.150 2.400 ;
    END
  END la_data_out[13]
  PIN la_data_out[14]
    DIRECTION OUTPUT ;
    USE SIGNAL ;
    PORT
      LAYER met2 ;
        RECT 1058.870 -4.800 1059.430 2.400 ;
    END
  END la_data_out[14]
  PIN la_data_out[15]
    DIRECTION OUTPUT ;
    USE SIGNAL ;
    PORT
      LAYER met2 ;
        RECT 1067.150 -4.800 1067.710 2.400 ;
    END
  END la_data_out[15]
  PIN la_data_out[16]
    DIRECTION OUTPUT ;
    USE SIGNAL ;
    PORT
      LAYER met2 ;
        RECT 1075.430 -4.800 1075.990 2.400 ;
    END
  END la_data_out[16]
  PIN la_data_out[17]
    DIRECTION OUTPUT ;
    USE SIGNAL ;
    PORT
      LAYER met2 ;
        RECT 1083.710 -4.800 1084.270 2.400 ;
    END
  END la_data_out[17]
  PIN la_data_out[18]
    DIRECTION OUTPUT ;
    USE SIGNAL ;
    PORT
      LAYER met2 ;
        RECT 1091.990 -4.800 1092.550 2.400 ;
    END
  END la_data_out[18]
  PIN la_data_out[19]
    DIRECTION OUTPUT ;
    USE SIGNAL ;
    PORT
      LAYER met2 ;
        RECT 1100.270 -4.800 1100.830 2.400 ;
    END
  END la_data_out[19]
  PIN la_data_out[1]
    DIRECTION OUTPUT ;
    USE SIGNAL ;
    PORT
      LAYER met2 ;
        RECT 951.230 -4.800 951.790 2.400 ;
    END
  END la_data_out[1]
  PIN la_data_out[20]
    DIRECTION OUTPUT ;
    USE SIGNAL ;
    PORT
      LAYER met2 ;
        RECT 1108.550 -4.800 1109.110 2.400 ;
    END
  END la_data_out[20]
  PIN la_data_out[21]
    DIRECTION OUTPUT ;
    USE SIGNAL ;
    PORT
      LAYER met2 ;
        RECT 1116.830 -4.800 1117.390 2.400 ;
    END
  END la_data_out[21]
  PIN la_data_out[22]
    DIRECTION OUTPUT ;
    USE SIGNAL ;
    PORT
      LAYER met2 ;
        RECT 1125.110 -4.800 1125.670 2.400 ;
    END
  END la_data_out[22]
  PIN la_data_out[23]
    DIRECTION OUTPUT ;
    USE SIGNAL ;
    PORT
      LAYER met2 ;
        RECT 1133.390 -4.800 1133.950 2.400 ;
    END
  END la_data_out[23]
  PIN la_data_out[24]
    DIRECTION OUTPUT ;
    USE SIGNAL ;
    PORT
      LAYER met2 ;
        RECT 1141.670 -4.800 1142.230 2.400 ;
    END
  END la_data_out[24]
  PIN la_data_out[25]
    DIRECTION OUTPUT ;
    USE SIGNAL ;
    PORT
      LAYER met2 ;
        RECT 1149.950 -4.800 1150.510 2.400 ;
    END
  END la_data_out[25]
  PIN la_data_out[26]
    DIRECTION OUTPUT ;
    USE SIGNAL ;
    PORT
      LAYER met2 ;
        RECT 1158.230 -4.800 1158.790 2.400 ;
    END
  END la_data_out[26]
  PIN la_data_out[27]
    DIRECTION OUTPUT ;
    USE SIGNAL ;
    PORT
      LAYER met2 ;
        RECT 1166.510 -4.800 1167.070 2.400 ;
    END
  END la_data_out[27]
  PIN la_data_out[28]
    DIRECTION OUTPUT ;
    USE SIGNAL ;
    PORT
      LAYER met2 ;
        RECT 1174.790 -4.800 1175.350 2.400 ;
    END
  END la_data_out[28]
  PIN la_data_out[29]
    DIRECTION OUTPUT ;
    USE SIGNAL ;
    PORT
      LAYER met2 ;
        RECT 1183.070 -4.800 1183.630 2.400 ;
    END
  END la_data_out[29]
  PIN la_data_out[2]
    DIRECTION OUTPUT ;
    USE SIGNAL ;
    PORT
      LAYER met2 ;
        RECT 959.510 -4.800 960.070 2.400 ;
    END
  END la_data_out[2]
  PIN la_data_out[30]
    DIRECTION OUTPUT ;
    USE SIGNAL ;
    PORT
      LAYER met2 ;
        RECT 1191.350 -4.800 1191.910 2.400 ;
    END
  END la_data_out[30]
  PIN la_data_out[31]
    DIRECTION OUTPUT ;
    USE SIGNAL ;
    PORT
      LAYER met2 ;
        RECT 1199.630 -4.800 1200.190 2.400 ;
    END
  END la_data_out[31]
  PIN la_data_out[3]
    DIRECTION OUTPUT ;
    USE SIGNAL ;
    PORT
      LAYER met2 ;
        RECT 967.790 -4.800 968.350 2.400 ;
    END
  END la_data_out[3]
  PIN la_data_out[4]
    DIRECTION OUTPUT ;
    USE SIGNAL ;
    PORT
      LAYER met2 ;
        RECT 976.070 -4.800 976.630 2.400 ;
    END
  END la_data_out[4]
  PIN la_data_out[5]
    DIRECTION OUTPUT ;
    USE SIGNAL ;
    PORT
      LAYER met2 ;
        RECT 984.350 -4.800 984.910 2.400 ;
    END
  END la_data_out[5]
  PIN la_data_out[6]
    DIRECTION OUTPUT ;
    USE SIGNAL ;
    PORT
      LAYER met2 ;
        RECT 992.630 -4.800 993.190 2.400 ;
    END
  END la_data_out[6]
  PIN la_data_out[7]
    DIRECTION OUTPUT ;
    USE SIGNAL ;
    PORT
      LAYER met2 ;
        RECT 1000.910 -4.800 1001.470 2.400 ;
    END
  END la_data_out[7]
  PIN la_data_out[8]
    DIRECTION OUTPUT ;
    USE SIGNAL ;
    PORT
      LAYER met2 ;
        RECT 1009.190 -4.800 1009.750 2.400 ;
    END
  END la_data_out[8]
  PIN la_data_out[9]
    DIRECTION OUTPUT ;
    USE SIGNAL ;
    PORT
      LAYER met2 ;
        RECT 1017.470 -4.800 1018.030 2.400 ;
    END
  END la_data_out[9]
  PIN la_oenb[0]
    DIRECTION INPUT ;
    USE SIGNAL ;
    ANTENNAGATEAREA 0.126000 ;
    PORT
      LAYER met3 ;
        RECT 1297.600 24.220 1304.800 25.420 ;
    END
  END la_oenb[0]
  PIN la_oenb[10]
    DIRECTION INPUT ;
    USE SIGNAL ;
    ANTENNAGATEAREA 0.126000 ;
    ANTENNADIFFAREA 0.434700 ;
    PORT
      LAYER met3 ;
        RECT 1297.600 228.220 1304.800 229.420 ;
    END
  END la_oenb[10]
  PIN la_oenb[11]
    DIRECTION INPUT ;
    USE SIGNAL ;
    ANTENNAGATEAREA 0.126000 ;
    PORT
      LAYER met3 ;
        RECT 1297.600 248.620 1304.800 249.820 ;
    END
  END la_oenb[11]
  PIN la_oenb[12]
    DIRECTION INPUT ;
    USE SIGNAL ;
    ANTENNAGATEAREA 0.126000 ;
    ANTENNADIFFAREA 0.434700 ;
    PORT
      LAYER met3 ;
        RECT 1297.600 269.020 1304.800 270.220 ;
    END
  END la_oenb[12]
  PIN la_oenb[13]
    DIRECTION INPUT ;
    USE SIGNAL ;
    ANTENNAGATEAREA 0.126000 ;
    ANTENNADIFFAREA 0.434700 ;
    PORT
      LAYER met3 ;
        RECT 1297.600 289.420 1304.800 290.620 ;
    END
  END la_oenb[13]
  PIN la_oenb[14]
    DIRECTION INPUT ;
    USE SIGNAL ;
    ANTENNAGATEAREA 0.126000 ;
    PORT
      LAYER met3 ;
        RECT 1297.600 309.820 1304.800 311.020 ;
    END
  END la_oenb[14]
  PIN la_oenb[15]
    DIRECTION INPUT ;
    USE SIGNAL ;
    ANTENNAGATEAREA 0.126000 ;
    PORT
      LAYER met3 ;
        RECT 1297.600 330.220 1304.800 331.420 ;
    END
  END la_oenb[15]
  PIN la_oenb[16]
    DIRECTION INPUT ;
    USE SIGNAL ;
    ANTENNAGATEAREA 0.126000 ;
    PORT
      LAYER met3 ;
        RECT 1297.600 350.620 1304.800 351.820 ;
    END
  END la_oenb[16]
  PIN la_oenb[17]
    DIRECTION INPUT ;
    USE SIGNAL ;
    ANTENNAGATEAREA 0.126000 ;
    PORT
      LAYER met3 ;
        RECT 1297.600 371.020 1304.800 372.220 ;
    END
  END la_oenb[17]
  PIN la_oenb[18]
    DIRECTION INPUT ;
    USE SIGNAL ;
    ANTENNAGATEAREA 0.126000 ;
    PORT
      LAYER met3 ;
        RECT 1297.600 391.420 1304.800 392.620 ;
    END
  END la_oenb[18]
  PIN la_oenb[19]
    DIRECTION INPUT ;
    USE SIGNAL ;
    ANTENNAGATEAREA 0.126000 ;
    PORT
      LAYER met3 ;
        RECT 1297.600 411.820 1304.800 413.020 ;
    END
  END la_oenb[19]
  PIN la_oenb[1]
    DIRECTION INPUT ;
    USE SIGNAL ;
    ANTENNAGATEAREA 0.126000 ;
    PORT
      LAYER met3 ;
        RECT 1297.600 44.620 1304.800 45.820 ;
    END
  END la_oenb[1]
  PIN la_oenb[20]
    DIRECTION INPUT ;
    USE SIGNAL ;
    ANTENNAGATEAREA 0.126000 ;
    PORT
      LAYER met3 ;
        RECT 1297.600 432.220 1304.800 433.420 ;
    END
  END la_oenb[20]
  PIN la_oenb[21]
    DIRECTION INPUT ;
    USE SIGNAL ;
    ANTENNAGATEAREA 0.126000 ;
    PORT
      LAYER met3 ;
        RECT 1297.600 452.620 1304.800 453.820 ;
    END
  END la_oenb[21]
  PIN la_oenb[22]
    DIRECTION INPUT ;
    USE SIGNAL ;
    ANTENNAGATEAREA 0.126000 ;
    PORT
      LAYER met3 ;
        RECT 1297.600 473.020 1304.800 474.220 ;
    END
  END la_oenb[22]
  PIN la_oenb[23]
    DIRECTION INPUT ;
    USE SIGNAL ;
    ANTENNAGATEAREA 0.126000 ;
    PORT
      LAYER met3 ;
        RECT 1297.600 493.420 1304.800 494.620 ;
    END
  END la_oenb[23]
  PIN la_oenb[24]
    DIRECTION INPUT ;
    USE SIGNAL ;
    ANTENNAGATEAREA 0.126000 ;
    PORT
      LAYER met3 ;
        RECT 1297.600 513.820 1304.800 515.020 ;
    END
  END la_oenb[24]
  PIN la_oenb[25]
    DIRECTION INPUT ;
    USE SIGNAL ;
    ANTENNAGATEAREA 0.126000 ;
    PORT
      LAYER met3 ;
        RECT 1297.600 534.220 1304.800 535.420 ;
    END
  END la_oenb[25]
  PIN la_oenb[26]
    DIRECTION INPUT ;
    USE SIGNAL ;
    ANTENNAGATEAREA 0.126000 ;
    PORT
      LAYER met3 ;
        RECT 1297.600 554.620 1304.800 555.820 ;
    END
  END la_oenb[26]
  PIN la_oenb[27]
    DIRECTION INPUT ;
    USE SIGNAL ;
    ANTENNAGATEAREA 0.126000 ;
    PORT
      LAYER met3 ;
        RECT 1297.600 575.020 1304.800 576.220 ;
    END
  END la_oenb[27]
  PIN la_oenb[28]
    DIRECTION INPUT ;
    USE SIGNAL ;
    ANTENNAGATEAREA 0.126000 ;
    PORT
      LAYER met3 ;
        RECT 1297.600 595.420 1304.800 596.620 ;
    END
  END la_oenb[28]
  PIN la_oenb[29]
    DIRECTION INPUT ;
    USE SIGNAL ;
    ANTENNAGATEAREA 0.126000 ;
    PORT
      LAYER met3 ;
        RECT 1297.600 615.820 1304.800 617.020 ;
    END
  END la_oenb[29]
  PIN la_oenb[2]
    DIRECTION INPUT ;
    USE SIGNAL ;
    ANTENNAGATEAREA 0.126000 ;
    PORT
      LAYER met3 ;
        RECT 1297.600 65.020 1304.800 66.220 ;
    END
  END la_oenb[2]
  PIN la_oenb[30]
    DIRECTION INPUT ;
    USE SIGNAL ;
    ANTENNAGATEAREA 0.990000 ;
    PORT
      LAYER met3 ;
        RECT 1297.600 636.220 1304.800 637.420 ;
    END
  END la_oenb[30]
  PIN la_oenb[31]
    DIRECTION INPUT ;
    USE SIGNAL ;
    ANTENNAGATEAREA 0.126000 ;
    PORT
      LAYER met3 ;
        RECT 1297.600 656.620 1304.800 657.820 ;
    END
  END la_oenb[31]
  PIN la_oenb[3]
    DIRECTION INPUT ;
    USE SIGNAL ;
    ANTENNAGATEAREA 0.126000 ;
    PORT
      LAYER met3 ;
        RECT 1297.600 85.420 1304.800 86.620 ;
    END
  END la_oenb[3]
  PIN la_oenb[4]
    DIRECTION INPUT ;
    USE SIGNAL ;
    ANTENNAGATEAREA 0.126000 ;
    PORT
      LAYER met3 ;
        RECT 1297.600 105.820 1304.800 107.020 ;
    END
  END la_oenb[4]
  PIN la_oenb[5]
    DIRECTION INPUT ;
    USE SIGNAL ;
    ANTENNAGATEAREA 0.126000 ;
    PORT
      LAYER met3 ;
        RECT 1297.600 126.220 1304.800 127.420 ;
    END
  END la_oenb[5]
  PIN la_oenb[6]
    DIRECTION INPUT ;
    USE SIGNAL ;
    ANTENNAGATEAREA 0.126000 ;
    PORT
      LAYER met3 ;
        RECT 1297.600 146.620 1304.800 147.820 ;
    END
  END la_oenb[6]
  PIN la_oenb[7]
    DIRECTION INPUT ;
    USE SIGNAL ;
    ANTENNAGATEAREA 0.126000 ;
    PORT
      LAYER met3 ;
        RECT 1297.600 167.020 1304.800 168.220 ;
    END
  END la_oenb[7]
  PIN la_oenb[8]
    DIRECTION INPUT ;
    USE SIGNAL ;
    ANTENNAGATEAREA 0.126000 ;
    ANTENNADIFFAREA 0.434700 ;
    PORT
      LAYER met3 ;
        RECT 1297.600 187.420 1304.800 188.620 ;
    END
  END la_oenb[8]
  PIN la_oenb[9]
    DIRECTION INPUT ;
    USE SIGNAL ;
    ANTENNAGATEAREA 0.126000 ;
    PORT
      LAYER met3 ;
        RECT 1297.600 207.820 1304.800 209.020 ;
    END
  END la_oenb[9]
  PIN user_clock2
    DIRECTION INPUT ;
    USE SIGNAL ;
    PORT
      LAYER met2 ;
        RECT 1207.910 -4.800 1208.470 2.400 ;
    END
  END user_clock2
  PIN user_irq[0]
    DIRECTION OUTPUT ;
    USE SIGNAL ;
    PORT
      LAYER met2 ;
        RECT 1216.190 -4.800 1216.750 2.400 ;
    END
  END user_irq[0]
  PIN user_irq[1]
    DIRECTION OUTPUT ;
    USE SIGNAL ;
    PORT
      LAYER met2 ;
        RECT 1224.470 -4.800 1225.030 2.400 ;
    END
  END user_irq[1]
  PIN user_irq[2]
    DIRECTION OUTPUT ;
    USE SIGNAL ;
    PORT
      LAYER met2 ;
        RECT 1232.750 -4.800 1233.310 2.400 ;
    END
  END user_irq[2]
  PIN wb_clk_i
    DIRECTION INPUT ;
    USE SIGNAL ;
    ANTENNAGATEAREA 0.126000 ;
    ANTENNADIFFAREA 0.434700 ;
    PORT
      LAYER met2 ;
        RECT 65.270 -4.800 65.830 2.400 ;
    END
  END wb_clk_i
  PIN wb_rst_i
    DIRECTION INPUT ;
    USE SIGNAL ;
    ANTENNAGATEAREA 0.126000 ;
    PORT
      LAYER met2 ;
        RECT 73.550 -4.800 74.110 2.400 ;
    END
  END wb_rst_i
  PIN wbs_ack_o
    DIRECTION OUTPUT ;
    USE SIGNAL ;
    ANTENNADIFFAREA 2.673000 ;
    PORT
      LAYER met2 ;
        RECT 81.830 -4.800 82.390 2.400 ;
    END
  END wbs_ack_o
  PIN wbs_adr_i[0]
    DIRECTION INPUT ;
    USE SIGNAL ;
    PORT
      LAYER met2 ;
        RECT 114.950 -4.800 115.510 2.400 ;
    END
  END wbs_adr_i[0]
  PIN wbs_adr_i[10]
    DIRECTION INPUT ;
    USE SIGNAL ;
    PORT
      LAYER met2 ;
        RECT 396.470 -4.800 397.030 2.400 ;
    END
  END wbs_adr_i[10]
  PIN wbs_adr_i[11]
    DIRECTION INPUT ;
    USE SIGNAL ;
    PORT
      LAYER met2 ;
        RECT 421.310 -4.800 421.870 2.400 ;
    END
  END wbs_adr_i[11]
  PIN wbs_adr_i[12]
    DIRECTION INPUT ;
    USE SIGNAL ;
    PORT
      LAYER met2 ;
        RECT 446.150 -4.800 446.710 2.400 ;
    END
  END wbs_adr_i[12]
  PIN wbs_adr_i[13]
    DIRECTION INPUT ;
    USE SIGNAL ;
    PORT
      LAYER met2 ;
        RECT 470.990 -4.800 471.550 2.400 ;
    END
  END wbs_adr_i[13]
  PIN wbs_adr_i[14]
    DIRECTION INPUT ;
    USE SIGNAL ;
    PORT
      LAYER met2 ;
        RECT 495.830 -4.800 496.390 2.400 ;
    END
  END wbs_adr_i[14]
  PIN wbs_adr_i[15]
    DIRECTION INPUT ;
    USE SIGNAL ;
    PORT
      LAYER met2 ;
        RECT 520.670 -4.800 521.230 2.400 ;
    END
  END wbs_adr_i[15]
  PIN wbs_adr_i[16]
    DIRECTION INPUT ;
    USE SIGNAL ;
    PORT
      LAYER met2 ;
        RECT 545.510 -4.800 546.070 2.400 ;
    END
  END wbs_adr_i[16]
  PIN wbs_adr_i[17]
    DIRECTION INPUT ;
    USE SIGNAL ;
    PORT
      LAYER met2 ;
        RECT 570.350 -4.800 570.910 2.400 ;
    END
  END wbs_adr_i[17]
  PIN wbs_adr_i[18]
    DIRECTION INPUT ;
    USE SIGNAL ;
    PORT
      LAYER met2 ;
        RECT 595.190 -4.800 595.750 2.400 ;
    END
  END wbs_adr_i[18]
  PIN wbs_adr_i[19]
    DIRECTION INPUT ;
    USE SIGNAL ;
    PORT
      LAYER met2 ;
        RECT 620.030 -4.800 620.590 2.400 ;
    END
  END wbs_adr_i[19]
  PIN wbs_adr_i[1]
    DIRECTION INPUT ;
    USE SIGNAL ;
    PORT
      LAYER met2 ;
        RECT 148.070 -4.800 148.630 2.400 ;
    END
  END wbs_adr_i[1]
  PIN wbs_adr_i[20]
    DIRECTION INPUT ;
    USE SIGNAL ;
    PORT
      LAYER met2 ;
        RECT 644.870 -4.800 645.430 2.400 ;
    END
  END wbs_adr_i[20]
  PIN wbs_adr_i[21]
    DIRECTION INPUT ;
    USE SIGNAL ;
    PORT
      LAYER met2 ;
        RECT 669.710 -4.800 670.270 2.400 ;
    END
  END wbs_adr_i[21]
  PIN wbs_adr_i[22]
    DIRECTION INPUT ;
    USE SIGNAL ;
    PORT
      LAYER met2 ;
        RECT 694.550 -4.800 695.110 2.400 ;
    END
  END wbs_adr_i[22]
  PIN wbs_adr_i[23]
    DIRECTION INPUT ;
    USE SIGNAL ;
    PORT
      LAYER met2 ;
        RECT 719.390 -4.800 719.950 2.400 ;
    END
  END wbs_adr_i[23]
  PIN wbs_adr_i[24]
    DIRECTION INPUT ;
    USE SIGNAL ;
    PORT
      LAYER met2 ;
        RECT 744.230 -4.800 744.790 2.400 ;
    END
  END wbs_adr_i[24]
  PIN wbs_adr_i[25]
    DIRECTION INPUT ;
    USE SIGNAL ;
    PORT
      LAYER met2 ;
        RECT 769.070 -4.800 769.630 2.400 ;
    END
  END wbs_adr_i[25]
  PIN wbs_adr_i[26]
    DIRECTION INPUT ;
    USE SIGNAL ;
    PORT
      LAYER met2 ;
        RECT 793.910 -4.800 794.470 2.400 ;
    END
  END wbs_adr_i[26]
  PIN wbs_adr_i[27]
    DIRECTION INPUT ;
    USE SIGNAL ;
    PORT
      LAYER met2 ;
        RECT 818.750 -4.800 819.310 2.400 ;
    END
  END wbs_adr_i[27]
  PIN wbs_adr_i[28]
    DIRECTION INPUT ;
    USE SIGNAL ;
    PORT
      LAYER met2 ;
        RECT 843.590 -4.800 844.150 2.400 ;
    END
  END wbs_adr_i[28]
  PIN wbs_adr_i[29]
    DIRECTION INPUT ;
    USE SIGNAL ;
    PORT
      LAYER met2 ;
        RECT 868.430 -4.800 868.990 2.400 ;
    END
  END wbs_adr_i[29]
  PIN wbs_adr_i[2]
    DIRECTION INPUT ;
    USE SIGNAL ;
    PORT
      LAYER met2 ;
        RECT 181.190 -4.800 181.750 2.400 ;
    END
  END wbs_adr_i[2]
  PIN wbs_adr_i[30]
    DIRECTION INPUT ;
    USE SIGNAL ;
    PORT
      LAYER met2 ;
        RECT 893.270 -4.800 893.830 2.400 ;
    END
  END wbs_adr_i[30]
  PIN wbs_adr_i[31]
    DIRECTION INPUT ;
    USE SIGNAL ;
    PORT
      LAYER met2 ;
        RECT 918.110 -4.800 918.670 2.400 ;
    END
  END wbs_adr_i[31]
  PIN wbs_adr_i[3]
    DIRECTION INPUT ;
    USE SIGNAL ;
    PORT
      LAYER met2 ;
        RECT 214.310 -4.800 214.870 2.400 ;
    END
  END wbs_adr_i[3]
  PIN wbs_adr_i[4]
    DIRECTION INPUT ;
    USE SIGNAL ;
    PORT
      LAYER met2 ;
        RECT 247.430 -4.800 247.990 2.400 ;
    END
  END wbs_adr_i[4]
  PIN wbs_adr_i[5]
    DIRECTION INPUT ;
    USE SIGNAL ;
    PORT
      LAYER met2 ;
        RECT 272.270 -4.800 272.830 2.400 ;
    END
  END wbs_adr_i[5]
  PIN wbs_adr_i[6]
    DIRECTION INPUT ;
    USE SIGNAL ;
    PORT
      LAYER met2 ;
        RECT 297.110 -4.800 297.670 2.400 ;
    END
  END wbs_adr_i[6]
  PIN wbs_adr_i[7]
    DIRECTION INPUT ;
    USE SIGNAL ;
    PORT
      LAYER met2 ;
        RECT 321.950 -4.800 322.510 2.400 ;
    END
  END wbs_adr_i[7]
  PIN wbs_adr_i[8]
    DIRECTION INPUT ;
    USE SIGNAL ;
    PORT
      LAYER met2 ;
        RECT 346.790 -4.800 347.350 2.400 ;
    END
  END wbs_adr_i[8]
  PIN wbs_adr_i[9]
    DIRECTION INPUT ;
    USE SIGNAL ;
    PORT
      LAYER met2 ;
        RECT 371.630 -4.800 372.190 2.400 ;
    END
  END wbs_adr_i[9]
  PIN wbs_cyc_i
    DIRECTION INPUT ;
    USE SIGNAL ;
    ANTENNAGATEAREA 0.126000 ;
    PORT
      LAYER met2 ;
        RECT 90.110 -4.800 90.670 2.400 ;
    END
  END wbs_cyc_i
  PIN wbs_dat_i[0]
    DIRECTION INPUT ;
    USE SIGNAL ;
    ANTENNAGATEAREA 0.126000 ;
    PORT
      LAYER met2 ;
        RECT 123.230 -4.800 123.790 2.400 ;
    END
  END wbs_dat_i[0]
  PIN wbs_dat_i[10]
    DIRECTION INPUT ;
    USE SIGNAL ;
    ANTENNAGATEAREA 0.126000 ;
    PORT
      LAYER met2 ;
        RECT 404.750 -4.800 405.310 2.400 ;
    END
  END wbs_dat_i[10]
  PIN wbs_dat_i[11]
    DIRECTION INPUT ;
    USE SIGNAL ;
    ANTENNAGATEAREA 0.126000 ;
    PORT
      LAYER met2 ;
        RECT 429.590 -4.800 430.150 2.400 ;
    END
  END wbs_dat_i[11]
  PIN wbs_dat_i[12]
    DIRECTION INPUT ;
    USE SIGNAL ;
    ANTENNAGATEAREA 0.126000 ;
    PORT
      LAYER met2 ;
        RECT 454.430 -4.800 454.990 2.400 ;
    END
  END wbs_dat_i[12]
  PIN wbs_dat_i[13]
    DIRECTION INPUT ;
    USE SIGNAL ;
    ANTENNAGATEAREA 0.126000 ;
    PORT
      LAYER met2 ;
        RECT 479.270 -4.800 479.830 2.400 ;
    END
  END wbs_dat_i[13]
  PIN wbs_dat_i[14]
    DIRECTION INPUT ;
    USE SIGNAL ;
    ANTENNAGATEAREA 0.126000 ;
    PORT
      LAYER met2 ;
        RECT 504.110 -4.800 504.670 2.400 ;
    END
  END wbs_dat_i[14]
  PIN wbs_dat_i[15]
    DIRECTION INPUT ;
    USE SIGNAL ;
    ANTENNAGATEAREA 0.126000 ;
    PORT
      LAYER met2 ;
        RECT 528.950 -4.800 529.510 2.400 ;
    END
  END wbs_dat_i[15]
  PIN wbs_dat_i[16]
    DIRECTION INPUT ;
    USE SIGNAL ;
    ANTENNAGATEAREA 0.126000 ;
    PORT
      LAYER met2 ;
        RECT 553.790 -4.800 554.350 2.400 ;
    END
  END wbs_dat_i[16]
  PIN wbs_dat_i[17]
    DIRECTION INPUT ;
    USE SIGNAL ;
    ANTENNAGATEAREA 0.126000 ;
    PORT
      LAYER met2 ;
        RECT 578.630 -4.800 579.190 2.400 ;
    END
  END wbs_dat_i[17]
  PIN wbs_dat_i[18]
    DIRECTION INPUT ;
    USE SIGNAL ;
    ANTENNAGATEAREA 0.126000 ;
    PORT
      LAYER met2 ;
        RECT 603.470 -4.800 604.030 2.400 ;
    END
  END wbs_dat_i[18]
  PIN wbs_dat_i[19]
    DIRECTION INPUT ;
    USE SIGNAL ;
    ANTENNAGATEAREA 0.126000 ;
    PORT
      LAYER met2 ;
        RECT 628.310 -4.800 628.870 2.400 ;
    END
  END wbs_dat_i[19]
  PIN wbs_dat_i[1]
    DIRECTION INPUT ;
    USE SIGNAL ;
    ANTENNAGATEAREA 0.126000 ;
    PORT
      LAYER met2 ;
        RECT 156.350 -4.800 156.910 2.400 ;
    END
  END wbs_dat_i[1]
  PIN wbs_dat_i[20]
    DIRECTION INPUT ;
    USE SIGNAL ;
    ANTENNAGATEAREA 0.126000 ;
    PORT
      LAYER met2 ;
        RECT 653.150 -4.800 653.710 2.400 ;
    END
  END wbs_dat_i[20]
  PIN wbs_dat_i[21]
    DIRECTION INPUT ;
    USE SIGNAL ;
    ANTENNAGATEAREA 0.126000 ;
    PORT
      LAYER met2 ;
        RECT 677.990 -4.800 678.550 2.400 ;
    END
  END wbs_dat_i[21]
  PIN wbs_dat_i[22]
    DIRECTION INPUT ;
    USE SIGNAL ;
    ANTENNAGATEAREA 0.126000 ;
    PORT
      LAYER met2 ;
        RECT 702.830 -4.800 703.390 2.400 ;
    END
  END wbs_dat_i[22]
  PIN wbs_dat_i[23]
    DIRECTION INPUT ;
    USE SIGNAL ;
    ANTENNAGATEAREA 0.126000 ;
    PORT
      LAYER met2 ;
        RECT 727.670 -4.800 728.230 2.400 ;
    END
  END wbs_dat_i[23]
  PIN wbs_dat_i[24]
    DIRECTION INPUT ;
    USE SIGNAL ;
    ANTENNAGATEAREA 0.126000 ;
    PORT
      LAYER met2 ;
        RECT 752.510 -4.800 753.070 2.400 ;
    END
  END wbs_dat_i[24]
  PIN wbs_dat_i[25]
    DIRECTION INPUT ;
    USE SIGNAL ;
    ANTENNAGATEAREA 0.126000 ;
    PORT
      LAYER met2 ;
        RECT 777.350 -4.800 777.910 2.400 ;
    END
  END wbs_dat_i[25]
  PIN wbs_dat_i[26]
    DIRECTION INPUT ;
    USE SIGNAL ;
    ANTENNAGATEAREA 0.126000 ;
    PORT
      LAYER met2 ;
        RECT 802.190 -4.800 802.750 2.400 ;
    END
  END wbs_dat_i[26]
  PIN wbs_dat_i[27]
    DIRECTION INPUT ;
    USE SIGNAL ;
    ANTENNAGATEAREA 0.126000 ;
    PORT
      LAYER met2 ;
        RECT 827.030 -4.800 827.590 2.400 ;
    END
  END wbs_dat_i[27]
  PIN wbs_dat_i[28]
    DIRECTION INPUT ;
    USE SIGNAL ;
    ANTENNAGATEAREA 0.126000 ;
    PORT
      LAYER met2 ;
        RECT 851.870 -4.800 852.430 2.400 ;
    END
  END wbs_dat_i[28]
  PIN wbs_dat_i[29]
    DIRECTION INPUT ;
    USE SIGNAL ;
    ANTENNAGATEAREA 0.126000 ;
    PORT
      LAYER met2 ;
        RECT 876.710 -4.800 877.270 2.400 ;
    END
  END wbs_dat_i[29]
  PIN wbs_dat_i[2]
    DIRECTION INPUT ;
    USE SIGNAL ;
    ANTENNAGATEAREA 0.126000 ;
    PORT
      LAYER met2 ;
        RECT 189.470 -4.800 190.030 2.400 ;
    END
  END wbs_dat_i[2]
  PIN wbs_dat_i[30]
    DIRECTION INPUT ;
    USE SIGNAL ;
    PORT
      LAYER met2 ;
        RECT 901.550 -4.800 902.110 2.400 ;
    END
  END wbs_dat_i[30]
  PIN wbs_dat_i[31]
    DIRECTION INPUT ;
    USE SIGNAL ;
    PORT
      LAYER met2 ;
        RECT 926.390 -4.800 926.950 2.400 ;
    END
  END wbs_dat_i[31]
  PIN wbs_dat_i[3]
    DIRECTION INPUT ;
    USE SIGNAL ;
    ANTENNAGATEAREA 0.126000 ;
    PORT
      LAYER met2 ;
        RECT 222.590 -4.800 223.150 2.400 ;
    END
  END wbs_dat_i[3]
  PIN wbs_dat_i[4]
    DIRECTION INPUT ;
    USE SIGNAL ;
    ANTENNAGATEAREA 0.126000 ;
    PORT
      LAYER met2 ;
        RECT 255.710 -4.800 256.270 2.400 ;
    END
  END wbs_dat_i[4]
  PIN wbs_dat_i[5]
    DIRECTION INPUT ;
    USE SIGNAL ;
    ANTENNAGATEAREA 0.126000 ;
    PORT
      LAYER met2 ;
        RECT 280.550 -4.800 281.110 2.400 ;
    END
  END wbs_dat_i[5]
  PIN wbs_dat_i[6]
    DIRECTION INPUT ;
    USE SIGNAL ;
    ANTENNAGATEAREA 0.126000 ;
    PORT
      LAYER met2 ;
        RECT 305.390 -4.800 305.950 2.400 ;
    END
  END wbs_dat_i[6]
  PIN wbs_dat_i[7]
    DIRECTION INPUT ;
    USE SIGNAL ;
    ANTENNAGATEAREA 0.126000 ;
    PORT
      LAYER met2 ;
        RECT 330.230 -4.800 330.790 2.400 ;
    END
  END wbs_dat_i[7]
  PIN wbs_dat_i[8]
    DIRECTION INPUT ;
    USE SIGNAL ;
    ANTENNAGATEAREA 0.126000 ;
    PORT
      LAYER met2 ;
        RECT 355.070 -4.800 355.630 2.400 ;
    END
  END wbs_dat_i[8]
  PIN wbs_dat_i[9]
    DIRECTION INPUT ;
    USE SIGNAL ;
    ANTENNAGATEAREA 0.126000 ;
    PORT
      LAYER met2 ;
        RECT 379.910 -4.800 380.470 2.400 ;
    END
  END wbs_dat_i[9]
  PIN wbs_dat_o[0]
    DIRECTION OUTPUT ;
    USE SIGNAL ;
    ANTENNADIFFAREA 2.673000 ;
    PORT
      LAYER met2 ;
        RECT 131.510 -4.800 132.070 2.400 ;
    END
  END wbs_dat_o[0]
  PIN wbs_dat_o[10]
    DIRECTION OUTPUT ;
    USE SIGNAL ;
    ANTENNADIFFAREA 2.673000 ;
    PORT
      LAYER met2 ;
        RECT 413.030 -4.800 413.590 2.400 ;
    END
  END wbs_dat_o[10]
  PIN wbs_dat_o[11]
    DIRECTION OUTPUT ;
    USE SIGNAL ;
    ANTENNADIFFAREA 2.673000 ;
    PORT
      LAYER met2 ;
        RECT 437.870 -4.800 438.430 2.400 ;
    END
  END wbs_dat_o[11]
  PIN wbs_dat_o[12]
    DIRECTION OUTPUT ;
    USE SIGNAL ;
    ANTENNADIFFAREA 2.673000 ;
    PORT
      LAYER met2 ;
        RECT 462.710 -4.800 463.270 2.400 ;
    END
  END wbs_dat_o[12]
  PIN wbs_dat_o[13]
    DIRECTION OUTPUT ;
    USE SIGNAL ;
    ANTENNADIFFAREA 2.673000 ;
    PORT
      LAYER met2 ;
        RECT 487.550 -4.800 488.110 2.400 ;
    END
  END wbs_dat_o[13]
  PIN wbs_dat_o[14]
    DIRECTION OUTPUT ;
    USE SIGNAL ;
    ANTENNADIFFAREA 2.673000 ;
    PORT
      LAYER met2 ;
        RECT 512.390 -4.800 512.950 2.400 ;
    END
  END wbs_dat_o[14]
  PIN wbs_dat_o[15]
    DIRECTION OUTPUT ;
    USE SIGNAL ;
    ANTENNADIFFAREA 2.673000 ;
    PORT
      LAYER met2 ;
        RECT 537.230 -4.800 537.790 2.400 ;
    END
  END wbs_dat_o[15]
  PIN wbs_dat_o[16]
    DIRECTION OUTPUT ;
    USE SIGNAL ;
    ANTENNADIFFAREA 2.673000 ;
    PORT
      LAYER met2 ;
        RECT 562.070 -4.800 562.630 2.400 ;
    END
  END wbs_dat_o[16]
  PIN wbs_dat_o[17]
    DIRECTION OUTPUT ;
    USE SIGNAL ;
    ANTENNADIFFAREA 2.673000 ;
    PORT
      LAYER met2 ;
        RECT 586.910 -4.800 587.470 2.400 ;
    END
  END wbs_dat_o[17]
  PIN wbs_dat_o[18]
    DIRECTION OUTPUT ;
    USE SIGNAL ;
    ANTENNADIFFAREA 2.673000 ;
    PORT
      LAYER met2 ;
        RECT 611.750 -4.800 612.310 2.400 ;
    END
  END wbs_dat_o[18]
  PIN wbs_dat_o[19]
    DIRECTION OUTPUT ;
    USE SIGNAL ;
    ANTENNADIFFAREA 2.673000 ;
    PORT
      LAYER met2 ;
        RECT 636.590 -4.800 637.150 2.400 ;
    END
  END wbs_dat_o[19]
  PIN wbs_dat_o[1]
    DIRECTION OUTPUT ;
    USE SIGNAL ;
    ANTENNADIFFAREA 2.673000 ;
    PORT
      LAYER met2 ;
        RECT 164.630 -4.800 165.190 2.400 ;
    END
  END wbs_dat_o[1]
  PIN wbs_dat_o[20]
    DIRECTION OUTPUT ;
    USE SIGNAL ;
    ANTENNADIFFAREA 2.673000 ;
    PORT
      LAYER met2 ;
        RECT 661.430 -4.800 661.990 2.400 ;
    END
  END wbs_dat_o[20]
  PIN wbs_dat_o[21]
    DIRECTION OUTPUT ;
    USE SIGNAL ;
    ANTENNADIFFAREA 2.673000 ;
    PORT
      LAYER met2 ;
        RECT 686.270 -4.800 686.830 2.400 ;
    END
  END wbs_dat_o[21]
  PIN wbs_dat_o[22]
    DIRECTION OUTPUT ;
    USE SIGNAL ;
    ANTENNADIFFAREA 2.673000 ;
    PORT
      LAYER met2 ;
        RECT 711.110 -4.800 711.670 2.400 ;
    END
  END wbs_dat_o[22]
  PIN wbs_dat_o[23]
    DIRECTION OUTPUT ;
    USE SIGNAL ;
    ANTENNADIFFAREA 2.673000 ;
    PORT
      LAYER met2 ;
        RECT 735.950 -4.800 736.510 2.400 ;
    END
  END wbs_dat_o[23]
  PIN wbs_dat_o[24]
    DIRECTION OUTPUT ;
    USE SIGNAL ;
    ANTENNADIFFAREA 2.673000 ;
    PORT
      LAYER met2 ;
        RECT 760.790 -4.800 761.350 2.400 ;
    END
  END wbs_dat_o[24]
  PIN wbs_dat_o[25]
    DIRECTION OUTPUT ;
    USE SIGNAL ;
    ANTENNADIFFAREA 2.673000 ;
    PORT
      LAYER met2 ;
        RECT 785.630 -4.800 786.190 2.400 ;
    END
  END wbs_dat_o[25]
  PIN wbs_dat_o[26]
    DIRECTION OUTPUT ;
    USE SIGNAL ;
    ANTENNADIFFAREA 2.673000 ;
    PORT
      LAYER met2 ;
        RECT 810.470 -4.800 811.030 2.400 ;
    END
  END wbs_dat_o[26]
  PIN wbs_dat_o[27]
    DIRECTION OUTPUT ;
    USE SIGNAL ;
    ANTENNADIFFAREA 2.673000 ;
    PORT
      LAYER met2 ;
        RECT 835.310 -4.800 835.870 2.400 ;
    END
  END wbs_dat_o[27]
  PIN wbs_dat_o[28]
    DIRECTION OUTPUT ;
    USE SIGNAL ;
    ANTENNADIFFAREA 2.673000 ;
    PORT
      LAYER met2 ;
        RECT 860.150 -4.800 860.710 2.400 ;
    END
  END wbs_dat_o[28]
  PIN wbs_dat_o[29]
    DIRECTION OUTPUT ;
    USE SIGNAL ;
    ANTENNADIFFAREA 2.673000 ;
    PORT
      LAYER met2 ;
        RECT 884.990 -4.800 885.550 2.400 ;
    END
  END wbs_dat_o[29]
  PIN wbs_dat_o[2]
    DIRECTION OUTPUT ;
    USE SIGNAL ;
    ANTENNADIFFAREA 2.673000 ;
    PORT
      LAYER met2 ;
        RECT 197.750 -4.800 198.310 2.400 ;
    END
  END wbs_dat_o[2]
  PIN wbs_dat_o[30]
    DIRECTION OUTPUT ;
    USE SIGNAL ;
    PORT
      LAYER met2 ;
        RECT 909.830 -4.800 910.390 2.400 ;
    END
  END wbs_dat_o[30]
  PIN wbs_dat_o[31]
    DIRECTION OUTPUT ;
    USE SIGNAL ;
    PORT
      LAYER met2 ;
        RECT 934.670 -4.800 935.230 2.400 ;
    END
  END wbs_dat_o[31]
  PIN wbs_dat_o[3]
    DIRECTION OUTPUT ;
    USE SIGNAL ;
    ANTENNADIFFAREA 2.673000 ;
    PORT
      LAYER met2 ;
        RECT 230.870 -4.800 231.430 2.400 ;
    END
  END wbs_dat_o[3]
  PIN wbs_dat_o[4]
    DIRECTION OUTPUT ;
    USE SIGNAL ;
    ANTENNADIFFAREA 2.673000 ;
    PORT
      LAYER met2 ;
        RECT 263.990 -4.800 264.550 2.400 ;
    END
  END wbs_dat_o[4]
  PIN wbs_dat_o[5]
    DIRECTION OUTPUT ;
    USE SIGNAL ;
    ANTENNADIFFAREA 2.673000 ;
    PORT
      LAYER met2 ;
        RECT 288.830 -4.800 289.390 2.400 ;
    END
  END wbs_dat_o[5]
  PIN wbs_dat_o[6]
    DIRECTION OUTPUT ;
    USE SIGNAL ;
    ANTENNADIFFAREA 2.673000 ;
    PORT
      LAYER met2 ;
        RECT 313.670 -4.800 314.230 2.400 ;
    END
  END wbs_dat_o[6]
  PIN wbs_dat_o[7]
    DIRECTION OUTPUT ;
    USE SIGNAL ;
    ANTENNADIFFAREA 2.673000 ;
    PORT
      LAYER met2 ;
        RECT 338.510 -4.800 339.070 2.400 ;
    END
  END wbs_dat_o[7]
  PIN wbs_dat_o[8]
    DIRECTION OUTPUT ;
    USE SIGNAL ;
    ANTENNADIFFAREA 2.673000 ;
    PORT
      LAYER met2 ;
        RECT 363.350 -4.800 363.910 2.400 ;
    END
  END wbs_dat_o[8]
  PIN wbs_dat_o[9]
    DIRECTION OUTPUT ;
    USE SIGNAL ;
    ANTENNADIFFAREA 2.673000 ;
    PORT
      LAYER met2 ;
        RECT 388.190 -4.800 388.750 2.400 ;
    END
  END wbs_dat_o[9]
  PIN wbs_sel_i[0]
    DIRECTION INPUT ;
    USE SIGNAL ;
    ANTENNAGATEAREA 0.126000 ;
    PORT
      LAYER met2 ;
        RECT 139.790 -4.800 140.350 2.400 ;
    END
  END wbs_sel_i[0]
  PIN wbs_sel_i[1]
    DIRECTION INPUT ;
    USE SIGNAL ;
    ANTENNAGATEAREA 0.126000 ;
    PORT
      LAYER met2 ;
        RECT 172.910 -4.800 173.470 2.400 ;
    END
  END wbs_sel_i[1]
  PIN wbs_sel_i[2]
    DIRECTION INPUT ;
    USE SIGNAL ;
    ANTENNAGATEAREA 0.126000 ;
    PORT
      LAYER met2 ;
        RECT 206.030 -4.800 206.590 2.400 ;
    END
  END wbs_sel_i[2]
  PIN wbs_sel_i[3]
    DIRECTION INPUT ;
    USE SIGNAL ;
    ANTENNAGATEAREA 0.126000 ;
    PORT
      LAYER met2 ;
        RECT 239.150 -4.800 239.710 2.400 ;
    END
  END wbs_sel_i[3]
  PIN wbs_stb_i
    DIRECTION INPUT ;
    USE SIGNAL ;
    ANTENNAGATEAREA 0.126000 ;
    PORT
      LAYER met2 ;
        RECT 98.390 -4.800 98.950 2.400 ;
    END
  END wbs_stb_i
  PIN wbs_we_i
    DIRECTION INPUT ;
    USE SIGNAL ;
    ANTENNAGATEAREA 0.126000 ;
    PORT
      LAYER met2 ;
        RECT 106.670 -4.800 107.230 2.400 ;
    END
  END wbs_we_i
  OBS
      LAYER li1 ;
        RECT 5.520 10.795 1294.440 1588.565 ;
      LAYER met1 ;
        RECT 2.370 10.640 1294.740 1588.720 ;
      LAYER met2 ;
        RECT 2.390 1597.320 27.270 1599.090 ;
        RECT 28.390 1597.320 75.110 1599.090 ;
        RECT 76.230 1597.320 122.950 1599.090 ;
        RECT 124.070 1597.320 170.790 1599.090 ;
        RECT 171.910 1597.320 218.630 1599.090 ;
        RECT 219.750 1597.320 266.470 1599.090 ;
        RECT 267.590 1597.320 314.310 1599.090 ;
        RECT 315.430 1597.320 362.150 1599.090 ;
        RECT 363.270 1597.320 409.990 1599.090 ;
        RECT 411.110 1597.320 457.830 1599.090 ;
        RECT 458.950 1597.320 505.670 1599.090 ;
        RECT 506.790 1597.320 553.510 1599.090 ;
        RECT 554.630 1597.320 601.350 1599.090 ;
        RECT 602.470 1597.320 649.190 1599.090 ;
        RECT 650.310 1597.320 697.030 1599.090 ;
        RECT 698.150 1597.320 744.870 1599.090 ;
        RECT 745.990 1597.320 792.710 1599.090 ;
        RECT 793.830 1597.320 840.550 1599.090 ;
        RECT 841.670 1597.320 888.390 1599.090 ;
        RECT 889.510 1597.320 936.230 1599.090 ;
        RECT 937.350 1597.320 984.070 1599.090 ;
        RECT 985.190 1597.320 1031.910 1599.090 ;
        RECT 1033.030 1597.320 1079.750 1599.090 ;
        RECT 1080.870 1597.320 1127.590 1599.090 ;
        RECT 1128.710 1597.320 1175.430 1599.090 ;
        RECT 1176.550 1597.320 1223.270 1599.090 ;
        RECT 1224.390 1597.320 1271.110 1599.090 ;
        RECT 1272.230 1597.320 1293.430 1599.090 ;
        RECT 2.390 2.680 1293.430 1597.320 ;
        RECT 2.390 0.950 64.990 2.680 ;
        RECT 66.110 0.950 73.270 2.680 ;
        RECT 74.390 0.950 81.550 2.680 ;
        RECT 82.670 0.950 89.830 2.680 ;
        RECT 90.950 0.950 98.110 2.680 ;
        RECT 99.230 0.950 106.390 2.680 ;
        RECT 107.510 0.950 114.670 2.680 ;
        RECT 115.790 0.950 122.950 2.680 ;
        RECT 124.070 0.950 131.230 2.680 ;
        RECT 132.350 0.950 139.510 2.680 ;
        RECT 140.630 0.950 147.790 2.680 ;
        RECT 148.910 0.950 156.070 2.680 ;
        RECT 157.190 0.950 164.350 2.680 ;
        RECT 165.470 0.950 172.630 2.680 ;
        RECT 173.750 0.950 180.910 2.680 ;
        RECT 182.030 0.950 189.190 2.680 ;
        RECT 190.310 0.950 197.470 2.680 ;
        RECT 198.590 0.950 205.750 2.680 ;
        RECT 206.870 0.950 214.030 2.680 ;
        RECT 215.150 0.950 222.310 2.680 ;
        RECT 223.430 0.950 230.590 2.680 ;
        RECT 231.710 0.950 238.870 2.680 ;
        RECT 239.990 0.950 247.150 2.680 ;
        RECT 248.270 0.950 255.430 2.680 ;
        RECT 256.550 0.950 263.710 2.680 ;
        RECT 264.830 0.950 271.990 2.680 ;
        RECT 273.110 0.950 280.270 2.680 ;
        RECT 281.390 0.950 288.550 2.680 ;
        RECT 289.670 0.950 296.830 2.680 ;
        RECT 297.950 0.950 305.110 2.680 ;
        RECT 306.230 0.950 313.390 2.680 ;
        RECT 314.510 0.950 321.670 2.680 ;
        RECT 322.790 0.950 329.950 2.680 ;
        RECT 331.070 0.950 338.230 2.680 ;
        RECT 339.350 0.950 346.510 2.680 ;
        RECT 347.630 0.950 354.790 2.680 ;
        RECT 355.910 0.950 363.070 2.680 ;
        RECT 364.190 0.950 371.350 2.680 ;
        RECT 372.470 0.950 379.630 2.680 ;
        RECT 380.750 0.950 387.910 2.680 ;
        RECT 389.030 0.950 396.190 2.680 ;
        RECT 397.310 0.950 404.470 2.680 ;
        RECT 405.590 0.950 412.750 2.680 ;
        RECT 413.870 0.950 421.030 2.680 ;
        RECT 422.150 0.950 429.310 2.680 ;
        RECT 430.430 0.950 437.590 2.680 ;
        RECT 438.710 0.950 445.870 2.680 ;
        RECT 446.990 0.950 454.150 2.680 ;
        RECT 455.270 0.950 462.430 2.680 ;
        RECT 463.550 0.950 470.710 2.680 ;
        RECT 471.830 0.950 478.990 2.680 ;
        RECT 480.110 0.950 487.270 2.680 ;
        RECT 488.390 0.950 495.550 2.680 ;
        RECT 496.670 0.950 503.830 2.680 ;
        RECT 504.950 0.950 512.110 2.680 ;
        RECT 513.230 0.950 520.390 2.680 ;
        RECT 521.510 0.950 528.670 2.680 ;
        RECT 529.790 0.950 536.950 2.680 ;
        RECT 538.070 0.950 545.230 2.680 ;
        RECT 546.350 0.950 553.510 2.680 ;
        RECT 554.630 0.950 561.790 2.680 ;
        RECT 562.910 0.950 570.070 2.680 ;
        RECT 571.190 0.950 578.350 2.680 ;
        RECT 579.470 0.950 586.630 2.680 ;
        RECT 587.750 0.950 594.910 2.680 ;
        RECT 596.030 0.950 603.190 2.680 ;
        RECT 604.310 0.950 611.470 2.680 ;
        RECT 612.590 0.950 619.750 2.680 ;
        RECT 620.870 0.950 628.030 2.680 ;
        RECT 629.150 0.950 636.310 2.680 ;
        RECT 637.430 0.950 644.590 2.680 ;
        RECT 645.710 0.950 652.870 2.680 ;
        RECT 653.990 0.950 661.150 2.680 ;
        RECT 662.270 0.950 669.430 2.680 ;
        RECT 670.550 0.950 677.710 2.680 ;
        RECT 678.830 0.950 685.990 2.680 ;
        RECT 687.110 0.950 694.270 2.680 ;
        RECT 695.390 0.950 702.550 2.680 ;
        RECT 703.670 0.950 710.830 2.680 ;
        RECT 711.950 0.950 719.110 2.680 ;
        RECT 720.230 0.950 727.390 2.680 ;
        RECT 728.510 0.950 735.670 2.680 ;
        RECT 736.790 0.950 743.950 2.680 ;
        RECT 745.070 0.950 752.230 2.680 ;
        RECT 753.350 0.950 760.510 2.680 ;
        RECT 761.630 0.950 768.790 2.680 ;
        RECT 769.910 0.950 777.070 2.680 ;
        RECT 778.190 0.950 785.350 2.680 ;
        RECT 786.470 0.950 793.630 2.680 ;
        RECT 794.750 0.950 801.910 2.680 ;
        RECT 803.030 0.950 810.190 2.680 ;
        RECT 811.310 0.950 818.470 2.680 ;
        RECT 819.590 0.950 826.750 2.680 ;
        RECT 827.870 0.950 835.030 2.680 ;
        RECT 836.150 0.950 843.310 2.680 ;
        RECT 844.430 0.950 851.590 2.680 ;
        RECT 852.710 0.950 859.870 2.680 ;
        RECT 860.990 0.950 868.150 2.680 ;
        RECT 869.270 0.950 876.430 2.680 ;
        RECT 877.550 0.950 884.710 2.680 ;
        RECT 885.830 0.950 892.990 2.680 ;
        RECT 894.110 0.950 901.270 2.680 ;
        RECT 902.390 0.950 909.550 2.680 ;
        RECT 910.670 0.950 917.830 2.680 ;
        RECT 918.950 0.950 926.110 2.680 ;
        RECT 927.230 0.950 934.390 2.680 ;
        RECT 935.510 0.950 942.670 2.680 ;
        RECT 943.790 0.950 950.950 2.680 ;
        RECT 952.070 0.950 959.230 2.680 ;
        RECT 960.350 0.950 967.510 2.680 ;
        RECT 968.630 0.950 975.790 2.680 ;
        RECT 976.910 0.950 984.070 2.680 ;
        RECT 985.190 0.950 992.350 2.680 ;
        RECT 993.470 0.950 1000.630 2.680 ;
        RECT 1001.750 0.950 1008.910 2.680 ;
        RECT 1010.030 0.950 1017.190 2.680 ;
        RECT 1018.310 0.950 1025.470 2.680 ;
        RECT 1026.590 0.950 1033.750 2.680 ;
        RECT 1034.870 0.950 1042.030 2.680 ;
        RECT 1043.150 0.950 1050.310 2.680 ;
        RECT 1051.430 0.950 1058.590 2.680 ;
        RECT 1059.710 0.950 1066.870 2.680 ;
        RECT 1067.990 0.950 1075.150 2.680 ;
        RECT 1076.270 0.950 1083.430 2.680 ;
        RECT 1084.550 0.950 1091.710 2.680 ;
        RECT 1092.830 0.950 1099.990 2.680 ;
        RECT 1101.110 0.950 1108.270 2.680 ;
        RECT 1109.390 0.950 1116.550 2.680 ;
        RECT 1117.670 0.950 1124.830 2.680 ;
        RECT 1125.950 0.950 1133.110 2.680 ;
        RECT 1134.230 0.950 1141.390 2.680 ;
        RECT 1142.510 0.950 1149.670 2.680 ;
        RECT 1150.790 0.950 1157.950 2.680 ;
        RECT 1159.070 0.950 1166.230 2.680 ;
        RECT 1167.350 0.950 1174.510 2.680 ;
        RECT 1175.630 0.950 1182.790 2.680 ;
        RECT 1183.910 0.950 1191.070 2.680 ;
        RECT 1192.190 0.950 1199.350 2.680 ;
        RECT 1200.470 0.950 1207.630 2.680 ;
        RECT 1208.750 0.950 1215.910 2.680 ;
        RECT 1217.030 0.950 1224.190 2.680 ;
        RECT 1225.310 0.950 1232.470 2.680 ;
        RECT 1233.590 0.950 1293.430 2.680 ;
      LAYER met3 ;
        RECT 2.400 1576.220 1297.600 1588.645 ;
        RECT 2.400 1574.220 1297.200 1576.220 ;
        RECT 2.400 1555.820 1297.600 1574.220 ;
        RECT 2.400 1553.820 1297.200 1555.820 ;
        RECT 2.400 1551.740 1297.600 1553.820 ;
        RECT 2.800 1549.740 1297.600 1551.740 ;
        RECT 2.400 1535.420 1297.600 1549.740 ;
        RECT 2.400 1533.420 1297.200 1535.420 ;
        RECT 2.400 1529.300 1297.600 1533.420 ;
        RECT 2.800 1527.300 1297.600 1529.300 ;
        RECT 2.400 1515.020 1297.600 1527.300 ;
        RECT 2.400 1513.020 1297.200 1515.020 ;
        RECT 2.400 1506.860 1297.600 1513.020 ;
        RECT 2.800 1504.860 1297.600 1506.860 ;
        RECT 2.400 1494.620 1297.600 1504.860 ;
        RECT 2.400 1492.620 1297.200 1494.620 ;
        RECT 2.400 1484.420 1297.600 1492.620 ;
        RECT 2.800 1482.420 1297.600 1484.420 ;
        RECT 2.400 1474.220 1297.600 1482.420 ;
        RECT 2.400 1472.220 1297.200 1474.220 ;
        RECT 2.400 1461.980 1297.600 1472.220 ;
        RECT 2.800 1459.980 1297.600 1461.980 ;
        RECT 2.400 1453.820 1297.600 1459.980 ;
        RECT 2.400 1451.820 1297.200 1453.820 ;
        RECT 2.400 1439.540 1297.600 1451.820 ;
        RECT 2.800 1437.540 1297.600 1439.540 ;
        RECT 2.400 1433.420 1297.600 1437.540 ;
        RECT 2.400 1431.420 1297.200 1433.420 ;
        RECT 2.400 1417.100 1297.600 1431.420 ;
        RECT 2.800 1415.100 1297.600 1417.100 ;
        RECT 2.400 1413.020 1297.600 1415.100 ;
        RECT 2.400 1411.020 1297.200 1413.020 ;
        RECT 2.400 1394.660 1297.600 1411.020 ;
        RECT 2.800 1392.660 1297.600 1394.660 ;
        RECT 2.400 1392.620 1297.600 1392.660 ;
        RECT 2.400 1390.620 1297.200 1392.620 ;
        RECT 2.400 1372.220 1297.600 1390.620 ;
        RECT 2.800 1370.220 1297.200 1372.220 ;
        RECT 2.400 1351.820 1297.600 1370.220 ;
        RECT 2.400 1349.820 1297.200 1351.820 ;
        RECT 2.400 1349.780 1297.600 1349.820 ;
        RECT 2.800 1347.780 1297.600 1349.780 ;
        RECT 2.400 1331.420 1297.600 1347.780 ;
        RECT 2.400 1329.420 1297.200 1331.420 ;
        RECT 2.400 1327.340 1297.600 1329.420 ;
        RECT 2.800 1325.340 1297.600 1327.340 ;
        RECT 2.400 1311.020 1297.600 1325.340 ;
        RECT 2.400 1309.020 1297.200 1311.020 ;
        RECT 2.400 1304.900 1297.600 1309.020 ;
        RECT 2.800 1302.900 1297.600 1304.900 ;
        RECT 2.400 1290.620 1297.600 1302.900 ;
        RECT 2.400 1288.620 1297.200 1290.620 ;
        RECT 2.400 1282.460 1297.600 1288.620 ;
        RECT 2.800 1280.460 1297.600 1282.460 ;
        RECT 2.400 1270.220 1297.600 1280.460 ;
        RECT 2.400 1268.220 1297.200 1270.220 ;
        RECT 2.400 1260.020 1297.600 1268.220 ;
        RECT 2.800 1258.020 1297.600 1260.020 ;
        RECT 2.400 1249.820 1297.600 1258.020 ;
        RECT 2.400 1247.820 1297.200 1249.820 ;
        RECT 2.400 1237.580 1297.600 1247.820 ;
        RECT 2.800 1235.580 1297.600 1237.580 ;
        RECT 2.400 1229.420 1297.600 1235.580 ;
        RECT 2.400 1227.420 1297.200 1229.420 ;
        RECT 2.400 1215.140 1297.600 1227.420 ;
        RECT 2.800 1213.140 1297.600 1215.140 ;
        RECT 2.400 1209.020 1297.600 1213.140 ;
        RECT 2.400 1207.020 1297.200 1209.020 ;
        RECT 2.400 1192.700 1297.600 1207.020 ;
        RECT 2.800 1190.700 1297.600 1192.700 ;
        RECT 2.400 1188.620 1297.600 1190.700 ;
        RECT 2.400 1186.620 1297.200 1188.620 ;
        RECT 2.400 1170.260 1297.600 1186.620 ;
        RECT 2.800 1168.260 1297.600 1170.260 ;
        RECT 2.400 1168.220 1297.600 1168.260 ;
        RECT 2.400 1166.220 1297.200 1168.220 ;
        RECT 2.400 1147.820 1297.600 1166.220 ;
        RECT 2.800 1145.820 1297.200 1147.820 ;
        RECT 2.400 1127.420 1297.600 1145.820 ;
        RECT 2.400 1125.420 1297.200 1127.420 ;
        RECT 2.400 1125.380 1297.600 1125.420 ;
        RECT 2.800 1123.380 1297.600 1125.380 ;
        RECT 2.400 1107.020 1297.600 1123.380 ;
        RECT 2.400 1105.020 1297.200 1107.020 ;
        RECT 2.400 1102.940 1297.600 1105.020 ;
        RECT 2.800 1100.940 1297.600 1102.940 ;
        RECT 2.400 1086.620 1297.600 1100.940 ;
        RECT 2.400 1084.620 1297.200 1086.620 ;
        RECT 2.400 1080.500 1297.600 1084.620 ;
        RECT 2.800 1078.500 1297.600 1080.500 ;
        RECT 2.400 1066.220 1297.600 1078.500 ;
        RECT 2.400 1064.220 1297.200 1066.220 ;
        RECT 2.400 1058.060 1297.600 1064.220 ;
        RECT 2.800 1056.060 1297.600 1058.060 ;
        RECT 2.400 1045.820 1297.600 1056.060 ;
        RECT 2.400 1043.820 1297.200 1045.820 ;
        RECT 2.400 1035.620 1297.600 1043.820 ;
        RECT 2.800 1033.620 1297.600 1035.620 ;
        RECT 2.400 1025.420 1297.600 1033.620 ;
        RECT 2.400 1023.420 1297.200 1025.420 ;
        RECT 2.400 1013.180 1297.600 1023.420 ;
        RECT 2.800 1011.180 1297.600 1013.180 ;
        RECT 2.400 1005.020 1297.600 1011.180 ;
        RECT 2.400 1003.020 1297.200 1005.020 ;
        RECT 2.400 990.740 1297.600 1003.020 ;
        RECT 2.800 988.740 1297.600 990.740 ;
        RECT 2.400 984.620 1297.600 988.740 ;
        RECT 2.400 982.620 1297.200 984.620 ;
        RECT 2.400 968.300 1297.600 982.620 ;
        RECT 2.800 966.300 1297.600 968.300 ;
        RECT 2.400 964.220 1297.600 966.300 ;
        RECT 2.400 962.220 1297.200 964.220 ;
        RECT 2.400 945.860 1297.600 962.220 ;
        RECT 2.800 943.860 1297.600 945.860 ;
        RECT 2.400 943.820 1297.600 943.860 ;
        RECT 2.400 941.820 1297.200 943.820 ;
        RECT 2.400 923.420 1297.600 941.820 ;
        RECT 2.800 921.420 1297.200 923.420 ;
        RECT 2.400 903.020 1297.600 921.420 ;
        RECT 2.400 901.020 1297.200 903.020 ;
        RECT 2.400 900.980 1297.600 901.020 ;
        RECT 2.800 898.980 1297.600 900.980 ;
        RECT 2.400 882.620 1297.600 898.980 ;
        RECT 2.400 880.620 1297.200 882.620 ;
        RECT 2.400 878.540 1297.600 880.620 ;
        RECT 2.800 876.540 1297.600 878.540 ;
        RECT 2.400 862.220 1297.600 876.540 ;
        RECT 2.400 860.220 1297.200 862.220 ;
        RECT 2.400 856.100 1297.600 860.220 ;
        RECT 2.800 854.100 1297.600 856.100 ;
        RECT 2.400 841.820 1297.600 854.100 ;
        RECT 2.400 839.820 1297.200 841.820 ;
        RECT 2.400 833.660 1297.600 839.820 ;
        RECT 2.800 831.660 1297.600 833.660 ;
        RECT 2.400 821.420 1297.600 831.660 ;
        RECT 2.400 819.420 1297.200 821.420 ;
        RECT 2.400 811.220 1297.600 819.420 ;
        RECT 2.800 809.220 1297.600 811.220 ;
        RECT 2.400 801.020 1297.600 809.220 ;
        RECT 2.400 799.020 1297.200 801.020 ;
        RECT 2.400 788.780 1297.600 799.020 ;
        RECT 2.800 786.780 1297.600 788.780 ;
        RECT 2.400 780.620 1297.600 786.780 ;
        RECT 2.400 778.620 1297.200 780.620 ;
        RECT 2.400 766.340 1297.600 778.620 ;
        RECT 2.800 764.340 1297.600 766.340 ;
        RECT 2.400 760.220 1297.600 764.340 ;
        RECT 2.400 758.220 1297.200 760.220 ;
        RECT 2.400 743.900 1297.600 758.220 ;
        RECT 2.800 741.900 1297.600 743.900 ;
        RECT 2.400 739.820 1297.600 741.900 ;
        RECT 2.400 737.820 1297.200 739.820 ;
        RECT 2.400 721.460 1297.600 737.820 ;
        RECT 2.800 719.460 1297.600 721.460 ;
        RECT 2.400 719.420 1297.600 719.460 ;
        RECT 2.400 717.420 1297.200 719.420 ;
        RECT 2.400 699.020 1297.600 717.420 ;
        RECT 2.800 697.020 1297.200 699.020 ;
        RECT 2.400 678.620 1297.600 697.020 ;
        RECT 2.400 676.620 1297.200 678.620 ;
        RECT 2.400 676.580 1297.600 676.620 ;
        RECT 2.800 674.580 1297.600 676.580 ;
        RECT 2.400 658.220 1297.600 674.580 ;
        RECT 2.400 656.220 1297.200 658.220 ;
        RECT 2.400 654.140 1297.600 656.220 ;
        RECT 2.800 652.140 1297.600 654.140 ;
        RECT 2.400 637.820 1297.600 652.140 ;
        RECT 2.400 635.820 1297.200 637.820 ;
        RECT 2.400 631.700 1297.600 635.820 ;
        RECT 2.800 629.700 1297.600 631.700 ;
        RECT 2.400 617.420 1297.600 629.700 ;
        RECT 2.400 615.420 1297.200 617.420 ;
        RECT 2.400 609.260 1297.600 615.420 ;
        RECT 2.800 607.260 1297.600 609.260 ;
        RECT 2.400 597.020 1297.600 607.260 ;
        RECT 2.400 595.020 1297.200 597.020 ;
        RECT 2.400 586.820 1297.600 595.020 ;
        RECT 2.800 584.820 1297.600 586.820 ;
        RECT 2.400 576.620 1297.600 584.820 ;
        RECT 2.400 574.620 1297.200 576.620 ;
        RECT 2.400 564.380 1297.600 574.620 ;
        RECT 2.800 562.380 1297.600 564.380 ;
        RECT 2.400 556.220 1297.600 562.380 ;
        RECT 2.400 554.220 1297.200 556.220 ;
        RECT 2.400 541.940 1297.600 554.220 ;
        RECT 2.800 539.940 1297.600 541.940 ;
        RECT 2.400 535.820 1297.600 539.940 ;
        RECT 2.400 533.820 1297.200 535.820 ;
        RECT 2.400 519.500 1297.600 533.820 ;
        RECT 2.800 517.500 1297.600 519.500 ;
        RECT 2.400 515.420 1297.600 517.500 ;
        RECT 2.400 513.420 1297.200 515.420 ;
        RECT 2.400 497.060 1297.600 513.420 ;
        RECT 2.800 495.060 1297.600 497.060 ;
        RECT 2.400 495.020 1297.600 495.060 ;
        RECT 2.400 493.020 1297.200 495.020 ;
        RECT 2.400 474.620 1297.600 493.020 ;
        RECT 2.800 472.620 1297.200 474.620 ;
        RECT 2.400 454.220 1297.600 472.620 ;
        RECT 2.400 452.220 1297.200 454.220 ;
        RECT 2.400 452.180 1297.600 452.220 ;
        RECT 2.800 450.180 1297.600 452.180 ;
        RECT 2.400 433.820 1297.600 450.180 ;
        RECT 2.400 431.820 1297.200 433.820 ;
        RECT 2.400 429.740 1297.600 431.820 ;
        RECT 2.800 427.740 1297.600 429.740 ;
        RECT 2.400 413.420 1297.600 427.740 ;
        RECT 2.400 411.420 1297.200 413.420 ;
        RECT 2.400 407.300 1297.600 411.420 ;
        RECT 2.800 405.300 1297.600 407.300 ;
        RECT 2.400 393.020 1297.600 405.300 ;
        RECT 2.400 391.020 1297.200 393.020 ;
        RECT 2.400 384.860 1297.600 391.020 ;
        RECT 2.800 382.860 1297.600 384.860 ;
        RECT 2.400 372.620 1297.600 382.860 ;
        RECT 2.400 370.620 1297.200 372.620 ;
        RECT 2.400 362.420 1297.600 370.620 ;
        RECT 2.800 360.420 1297.600 362.420 ;
        RECT 2.400 352.220 1297.600 360.420 ;
        RECT 2.400 350.220 1297.200 352.220 ;
        RECT 2.400 339.980 1297.600 350.220 ;
        RECT 2.800 337.980 1297.600 339.980 ;
        RECT 2.400 331.820 1297.600 337.980 ;
        RECT 2.400 329.820 1297.200 331.820 ;
        RECT 2.400 317.540 1297.600 329.820 ;
        RECT 2.800 315.540 1297.600 317.540 ;
        RECT 2.400 311.420 1297.600 315.540 ;
        RECT 2.400 309.420 1297.200 311.420 ;
        RECT 2.400 295.100 1297.600 309.420 ;
        RECT 2.800 293.100 1297.600 295.100 ;
        RECT 2.400 291.020 1297.600 293.100 ;
        RECT 2.400 289.020 1297.200 291.020 ;
        RECT 2.400 272.660 1297.600 289.020 ;
        RECT 2.800 270.660 1297.600 272.660 ;
        RECT 2.400 270.620 1297.600 270.660 ;
        RECT 2.400 268.620 1297.200 270.620 ;
        RECT 2.400 250.220 1297.600 268.620 ;
        RECT 2.800 248.220 1297.200 250.220 ;
        RECT 2.400 229.820 1297.600 248.220 ;
        RECT 2.400 227.820 1297.200 229.820 ;
        RECT 2.400 227.780 1297.600 227.820 ;
        RECT 2.800 225.780 1297.600 227.780 ;
        RECT 2.400 209.420 1297.600 225.780 ;
        RECT 2.400 207.420 1297.200 209.420 ;
        RECT 2.400 205.340 1297.600 207.420 ;
        RECT 2.800 203.340 1297.600 205.340 ;
        RECT 2.400 189.020 1297.600 203.340 ;
        RECT 2.400 187.020 1297.200 189.020 ;
        RECT 2.400 182.900 1297.600 187.020 ;
        RECT 2.800 180.900 1297.600 182.900 ;
        RECT 2.400 168.620 1297.600 180.900 ;
        RECT 2.400 166.620 1297.200 168.620 ;
        RECT 2.400 160.460 1297.600 166.620 ;
        RECT 2.800 158.460 1297.600 160.460 ;
        RECT 2.400 148.220 1297.600 158.460 ;
        RECT 2.400 146.220 1297.200 148.220 ;
        RECT 2.400 138.020 1297.600 146.220 ;
        RECT 2.800 136.020 1297.600 138.020 ;
        RECT 2.400 127.820 1297.600 136.020 ;
        RECT 2.400 125.820 1297.200 127.820 ;
        RECT 2.400 115.580 1297.600 125.820 ;
        RECT 2.800 113.580 1297.600 115.580 ;
        RECT 2.400 107.420 1297.600 113.580 ;
        RECT 2.400 105.420 1297.200 107.420 ;
        RECT 2.400 93.140 1297.600 105.420 ;
        RECT 2.800 91.140 1297.600 93.140 ;
        RECT 2.400 87.020 1297.600 91.140 ;
        RECT 2.400 85.020 1297.200 87.020 ;
        RECT 2.400 70.700 1297.600 85.020 ;
        RECT 2.800 68.700 1297.600 70.700 ;
        RECT 2.400 66.620 1297.600 68.700 ;
        RECT 2.400 64.620 1297.200 66.620 ;
        RECT 2.400 48.260 1297.600 64.620 ;
        RECT 2.800 46.260 1297.600 48.260 ;
        RECT 2.400 46.220 1297.600 46.260 ;
        RECT 2.400 44.220 1297.200 46.220 ;
        RECT 2.400 25.820 1297.600 44.220 ;
        RECT 2.400 23.820 1297.200 25.820 ;
        RECT 2.400 10.715 1297.600 23.820 ;
      LAYER met4 ;
        RECT 72.975 17.175 98.570 1126.585 ;
        RECT 102.470 17.175 128.570 1126.585 ;
        RECT 132.470 17.175 158.570 1126.585 ;
        RECT 162.470 17.175 188.570 1126.585 ;
        RECT 192.470 17.175 218.570 1126.585 ;
        RECT 222.470 17.175 248.570 1126.585 ;
        RECT 252.470 17.175 278.570 1126.585 ;
        RECT 282.470 17.175 308.570 1126.585 ;
        RECT 312.470 17.175 338.570 1126.585 ;
        RECT 342.470 17.175 368.570 1126.585 ;
        RECT 372.470 17.175 398.570 1126.585 ;
        RECT 402.470 17.175 428.570 1126.585 ;
        RECT 432.470 17.175 458.570 1126.585 ;
        RECT 462.470 17.175 488.570 1126.585 ;
        RECT 492.470 17.175 518.570 1126.585 ;
        RECT 522.470 17.175 548.570 1126.585 ;
        RECT 552.470 17.175 578.570 1126.585 ;
        RECT 582.470 17.175 608.570 1126.585 ;
        RECT 612.470 17.175 638.570 1126.585 ;
        RECT 642.470 17.175 668.570 1126.585 ;
        RECT 672.470 17.175 698.570 1126.585 ;
        RECT 702.470 17.175 728.570 1126.585 ;
        RECT 732.470 17.175 758.570 1126.585 ;
        RECT 762.470 17.175 788.570 1126.585 ;
        RECT 792.470 17.175 818.570 1126.585 ;
        RECT 822.470 17.175 848.570 1126.585 ;
        RECT 852.470 17.175 878.570 1126.585 ;
        RECT 882.470 17.175 908.570 1126.585 ;
        RECT 912.470 17.175 938.570 1126.585 ;
        RECT 942.470 17.175 968.570 1126.585 ;
        RECT 972.470 17.175 998.570 1126.585 ;
        RECT 1002.470 17.175 1028.570 1126.585 ;
        RECT 1032.470 17.175 1058.570 1126.585 ;
        RECT 1062.470 17.175 1088.570 1126.585 ;
        RECT 1092.470 17.175 1118.570 1126.585 ;
        RECT 1122.470 17.175 1148.570 1126.585 ;
        RECT 1152.470 17.175 1178.570 1126.585 ;
        RECT 1182.470 17.175 1208.570 1126.585 ;
        RECT 1212.470 17.175 1238.570 1126.585 ;
        RECT 1242.470 17.175 1268.570 1126.585 ;
        RECT 1272.470 17.175 1285.865 1126.585 ;
  END
END user_project
END LIBRARY

